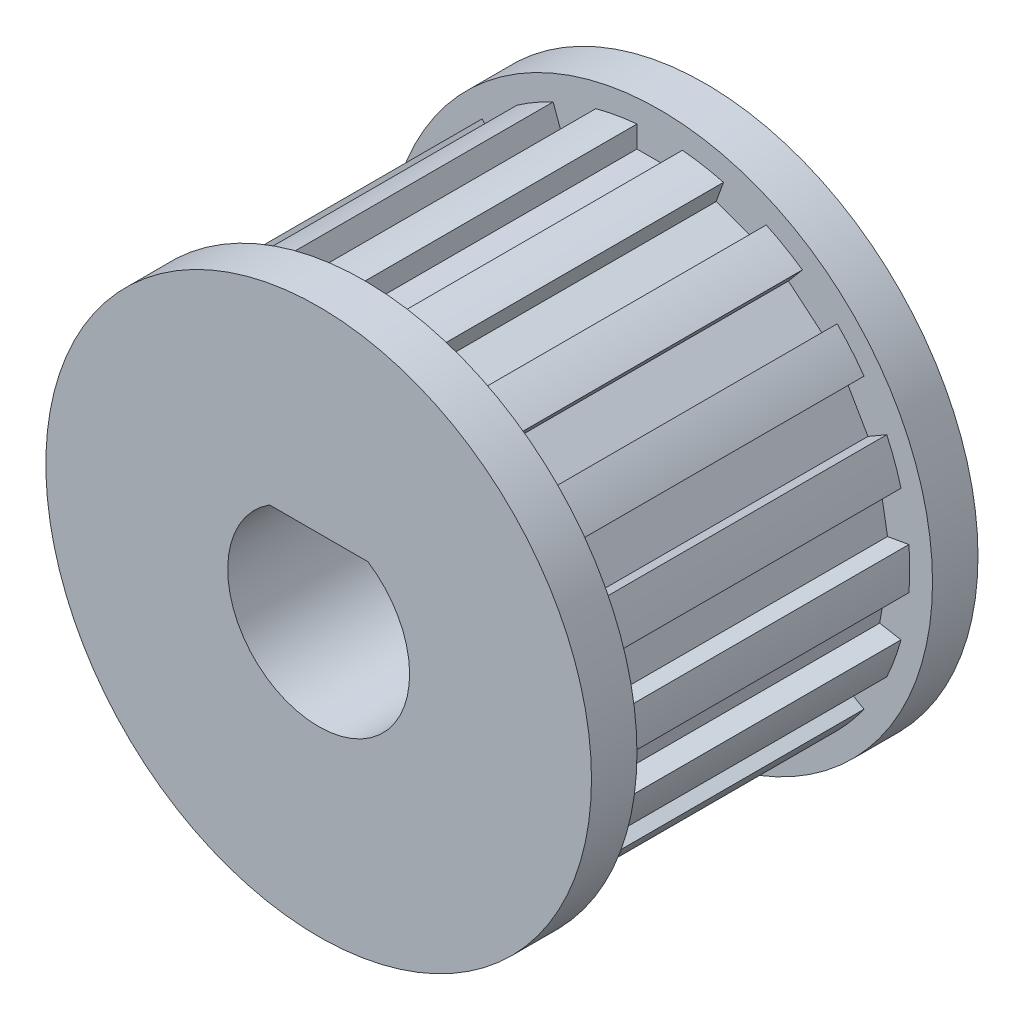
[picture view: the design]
ISO-10303-21;
HEADER;
FILE_DESCRIPTION(('STEP AP214'),'2;1');
FILE_NAME('part.step','',(''),(''),'','','');
FILE_SCHEMA(('AUTOMOTIVE_DESIGN { 1 0 10303 214 1 1 1 1 }'));
ENDSEC;
DATA;
#1=APPLICATION_CONTEXT('core data for automotive mechanical design processes');
#2=APPLICATION_PROTOCOL_DEFINITION('international standard','automotive_design',2000,#1);
#3=PRODUCT_CONTEXT('',#1,'mechanical');
#4=PRODUCT('Part','Part','',(#3));
#5=PRODUCT_RELATED_PRODUCT_CATEGORY('part','',(#4));
#6=PRODUCT_DEFINITION_FORMATION('','',#4);
#7=PRODUCT_DEFINITION_CONTEXT('part definition',#1,'design');
#8=PRODUCT_DEFINITION('design','',#6,#7);
#9=PRODUCT_DEFINITION_SHAPE('','',#8);
#10=(LENGTH_UNIT() NAMED_UNIT(*) SI_UNIT(.MILLI.,.METRE.));
#11=(NAMED_UNIT(*) PLANE_ANGLE_UNIT() SI_UNIT($,.RADIAN.));
#12=(NAMED_UNIT(*) SI_UNIT($,.STERADIAN.) SOLID_ANGLE_UNIT());
#13=UNCERTAINTY_MEASURE_WITH_UNIT(LENGTH_MEASURE(1.E-05),#10,'distance_accuracy_value','');
#14=(GEOMETRIC_REPRESENTATION_CONTEXT(3) GLOBAL_UNCERTAINTY_ASSIGNED_CONTEXT((#13)) GLOBAL_UNIT_ASSIGNED_CONTEXT((#10,
#11,#12)) REPRESENTATION_CONTEXT('',''));
#15=CARTESIAN_POINT('',(0.,0.,0.));
#16=DIRECTION('',(0.,0.,1.));
#17=DIRECTION('',(1.,0.,0.));
#18=AXIS2_PLACEMENT_3D('',#15,#16,#17);
#19=CARTESIAN_POINT('',(0.,0.,7.5));
#20=DIRECTION('',(0.,0.,-1.));
#21=DIRECTION('',(-1.,0.,0.));
#22=AXIS2_PLACEMENT_3D('',#19,#20,#21);
#23=CYLINDRICAL_SURFACE('',#22,5.5);
#24=CARTESIAN_POINT('',(0.,0.,7.5));
#25=DIRECTION('',(0.,0.,1.));
#26=DIRECTION('',(1.,0.,0.));
#27=AXIS2_PLACEMENT_3D('',#24,#25,#26);
#28=CIRCLE('',#27,5.5);
#29=CARTESIAN_POINT('',(1.40347516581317,5.31791852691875,7.5));
#30=VERTEX_POINT('',#29);
#31=CARTESIAN_POINT('',(0.500000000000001,5.47722557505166,7.5));
#32=VERTEX_POINT('',#31);
#33=EDGE_CURVE('E982',#30,#32,#28,.T.);
#34=ORIENTED_EDGE('',*,*,#33,.F.);
#35=DIRECTION('',(0.,0.,-1.));
#36=VECTOR('',#35,1.);
#37=CARTESIAN_POINT('',(1.40347516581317,5.31791852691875,7.5));
#38=LINE('',#37,#36);
#39=CARTESIAN_POINT('',(1.40347516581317,5.31791852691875,1.));
#40=VERTEX_POINT('',#39);
#41=EDGE_CURVE('E523',#30,#40,#38,.T.);
#42=ORIENTED_EDGE('',*,*,#41,.T.);
#43=CARTESIAN_POINT('',(0.,0.,1.));
#44=DIRECTION('',(0.,0.,1.));
#45=DIRECTION('',(1.,0.,0.));
#46=AXIS2_PLACEMENT_3D('',#43,#44,#45);
#47=CIRCLE('',#46,5.5);
#48=CARTESIAN_POINT('',(0.500000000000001,5.47722557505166,1.));
#49=VERTEX_POINT('',#48);
#50=EDGE_CURVE('E978',#40,#49,#47,.T.);
#51=ORIENTED_EDGE('',*,*,#50,.T.);
#52=DIRECTION('',(0.,0.,-1.));
#53=VECTOR('',#52,1.);
#54=CARTESIAN_POINT('',(0.5,5.47722557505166,7.5));
#55=LINE('',#54,#53);
#56=EDGE_CURVE('E994',#49,#32,#55,.F.);
#57=ORIENTED_EDGE('',*,*,#56,.T.);
#58=EDGE_LOOP('',(#34,#42,#51,#57));
#59=FACE_BOUND('',#58,.T.);
#60=ADVANCED_FACE('F30',(#59),#23,.T.);
#61=CARTESIAN_POINT('',(3.1376705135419,4.51719202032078,1.));
#62=VERTEX_POINT('',#61);
#63=CARTESIAN_POINT('',(2.34316778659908,4.97589838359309,1.));
#64=VERTEX_POINT('',#63);
#65=EDGE_CURVE('E1085',#62,#64,#47,.T.);
#66=ORIENTED_EDGE('',*,*,#65,.T.);
#67=DIRECTION('',(0.,0.,-1.));
#68=VECTOR('',#67,1.);
#69=CARTESIAN_POINT('',(2.34316778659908,4.97589838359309,7.5));
#70=LINE('',#69,#68);
#71=CARTESIAN_POINT('',(2.34316778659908,4.97589838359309,7.5));
#72=VERTEX_POINT('',#71);
#73=EDGE_CURVE('E496',#64,#72,#70,.F.);
#74=ORIENTED_EDGE('',*,*,#73,.T.);
#75=CARTESIAN_POINT('',(3.1376705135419,4.51719202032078,7.5));
#76=VERTEX_POINT('',#75);
#77=EDGE_CURVE('E1073',#76,#72,#28,.T.);
#78=ORIENTED_EDGE('',*,*,#77,.F.);
#79=DIRECTION('',(0.,0.,-1.));
#80=VECTOR('',#79,1.);
#81=CARTESIAN_POINT('',(3.1376705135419,4.51719202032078,7.5));
#82=LINE('',#81,#80);
#83=EDGE_CURVE('E547',#76,#62,#82,.T.);
#84=ORIENTED_EDGE('',*,*,#83,.T.);
#85=EDGE_LOOP('',(#66,#74,#78,#84));
#86=FACE_BOUND('',#85,.T.);
#87=ADVANCED_FACE('F1099',(#86),#23,.T.);
#88=CARTESIAN_POINT('',(4.49341649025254,3.1716254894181,1.));
#89=VERTEX_POINT('',#88);
#90=CARTESIAN_POINT('',(3.90371495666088,3.87440441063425,1.));
#91=VERTEX_POINT('',#90);
#92=EDGE_CURVE('E1184',#89,#91,#47,.T.);
#93=ORIENTED_EDGE('',*,*,#92,.T.);
#94=DIRECTION('',(0.,0.,-1.));
#95=VECTOR('',#94,1.);
#96=CARTESIAN_POINT('',(3.90371495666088,3.87440441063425,7.5));
#97=LINE('',#96,#95);
#98=CARTESIAN_POINT('',(3.90371495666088,3.87440441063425,7.5));
#99=VERTEX_POINT('',#98);
#100=EDGE_CURVE('E543',#91,#99,#97,.F.);
#101=ORIENTED_EDGE('',*,*,#100,.T.);
#102=CARTESIAN_POINT('',(4.49341649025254,3.1716254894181,7.5));
#103=VERTEX_POINT('',#102);
#104=EDGE_CURVE('E1070',#103,#99,#28,.T.);
#105=ORIENTED_EDGE('',*,*,#104,.F.);
#106=DIRECTION('',(0.,0.,-1.));
#107=VECTOR('',#106,1.);
#108=CARTESIAN_POINT('',(4.49341649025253,3.1716254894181,7.5));
#109=LINE('',#108,#107);
#110=EDGE_CURVE('E573',#103,#89,#109,.T.);
#111=ORIENTED_EDGE('',*,*,#110,.T.);
#112=EDGE_LOOP('',(#93,#101,#105,#111));
#113=FACE_BOUND('',#112,.T.);
#114=ADVANCED_FACE('F1104',(#113),#23,.T.);
#115=CARTESIAN_POINT('',(5.30719012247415,1.44351411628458,1.));
#116=VERTEX_POINT('',#115);
#117=CARTESIAN_POINT('',(4.99341649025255,2.30560008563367,1.));
#118=VERTEX_POINT('',#117);
#119=EDGE_CURVE('E1180',#116,#118,#47,.T.);
#120=ORIENTED_EDGE('',*,*,#119,.T.);
#121=DIRECTION('',(0.,0.,-1.));
#122=VECTOR('',#121,1.);
#123=CARTESIAN_POINT('',(4.99341649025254,2.30560008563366,7.5));
#124=LINE('',#123,#122);
#125=CARTESIAN_POINT('',(4.99341649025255,2.30560008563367,7.5));
#126=VERTEX_POINT('',#125);
#127=EDGE_CURVE('E569',#118,#126,#124,.F.);
#128=ORIENTED_EDGE('',*,*,#127,.T.);
#129=CARTESIAN_POINT('',(5.30719012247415,1.44351411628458,7.5));
#130=VERTEX_POINT('',#129);
#131=EDGE_CURVE('E1067',#130,#126,#28,.T.);
#132=ORIENTED_EDGE('',*,*,#131,.F.);
#133=DIRECTION('',(0.,0.,-1.));
#134=VECTOR('',#133,1.);
#135=CARTESIAN_POINT('',(5.30719012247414,1.44351411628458,7.5));
#136=LINE('',#135,#134);
#137=EDGE_CURVE('E599',#130,#116,#136,.T.);
#138=ORIENTED_EDGE('',*,*,#137,.T.);
#139=EDGE_LOOP('',(#120,#128,#132,#138));
#140=FACE_BOUND('',#139,.T.);
#141=ADVANCED_FACE('F1451',(#140),#23,.T.);
#142=CARTESIAN_POINT('',(5.4808383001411,-0.458706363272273,1.));
#143=VERTEX_POINT('',#142);
#144=CARTESIAN_POINT('',(5.48083830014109,0.458706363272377,1.));
#145=VERTEX_POINT('',#144);
#146=EDGE_CURVE('E1176',#143,#145,#47,.T.);
#147=ORIENTED_EDGE('',*,*,#146,.T.);
#148=DIRECTION('',(0.,0.,-1.));
#149=VECTOR('',#148,1.);
#150=CARTESIAN_POINT('',(5.48083830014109,0.458706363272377,7.5));
#151=LINE('',#150,#149);
#152=CARTESIAN_POINT('',(5.48083830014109,0.458706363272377,7.5));
#153=VERTEX_POINT('',#152);
#154=EDGE_CURVE('E596',#145,#153,#151,.F.);
#155=ORIENTED_EDGE('',*,*,#154,.T.);
#156=CARTESIAN_POINT('',(5.4808383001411,-0.458706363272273,7.5));
#157=VERTEX_POINT('',#156);
#158=EDGE_CURVE('E1064',#157,#153,#28,.T.);
#159=ORIENTED_EDGE('',*,*,#158,.F.);
#160=DIRECTION('',(0.,0.,-1.));
#161=VECTOR('',#160,1.);
#162=CARTESIAN_POINT('',(5.48083830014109,-0.458706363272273,7.5));
#163=LINE('',#162,#161);
#164=EDGE_CURVE('E625',#157,#143,#163,.T.);
#165=ORIENTED_EDGE('',*,*,#164,.T.);
#166=EDGE_LOOP('',(#147,#155,#159,#165));
#167=FACE_BOUND('',#166,.T.);
#168=ADVANCED_FACE('F1445',(#167),#23,.T.);
#169=CARTESIAN_POINT('',(4.99341649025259,-2.30560008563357,1.));
#170=VERTEX_POINT('',#169);
#171=CARTESIAN_POINT('',(5.30719012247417,-1.44351411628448,1.));
#172=VERTEX_POINT('',#171);
#173=EDGE_CURVE('E1172',#170,#172,#47,.T.);
#174=ORIENTED_EDGE('',*,*,#173,.T.);
#175=DIRECTION('',(0.,0.,-1.));
#176=VECTOR('',#175,1.);
#177=CARTESIAN_POINT('',(5.30719012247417,-1.44351411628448,7.5));
#178=LINE('',#177,#176);
#179=CARTESIAN_POINT('',(5.30719012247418,-1.44351411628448,7.5));
#180=VERTEX_POINT('',#179);
#181=EDGE_CURVE('E621',#172,#180,#178,.F.);
#182=ORIENTED_EDGE('',*,*,#181,.T.);
#183=CARTESIAN_POINT('',(4.99341649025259,-2.30560008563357,7.5));
#184=VERTEX_POINT('',#183);
#185=EDGE_CURVE('E1061',#184,#180,#28,.T.);
#186=ORIENTED_EDGE('',*,*,#185,.F.);
#187=DIRECTION('',(0.,0.,-1.));
#188=VECTOR('',#187,1.);
#189=CARTESIAN_POINT('',(4.99341649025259,-2.30560008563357,7.5));
#190=LINE('',#189,#188);
#191=EDGE_CURVE('E651',#184,#170,#190,.T.);
#192=ORIENTED_EDGE('',*,*,#191,.T.);
#193=EDGE_LOOP('',(#174,#182,#186,#192));
#194=FACE_BOUND('',#193,.T.);
#195=ADVANCED_FACE('F1439',(#194),#23,.T.);
#196=CARTESIAN_POINT('',(3.90371495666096,-3.87440441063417,1.));
#197=VERTEX_POINT('',#196);
#198=CARTESIAN_POINT('',(4.4934164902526,-3.17162548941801,1.));
#199=VERTEX_POINT('',#198);
#200=EDGE_CURVE('E1168',#197,#199,#47,.T.);
#201=ORIENTED_EDGE('',*,*,#200,.T.);
#202=DIRECTION('',(0.,0.,-1.));
#203=VECTOR('',#202,1.);
#204=CARTESIAN_POINT('',(4.4934164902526,-3.17162548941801,7.5));
#205=LINE('',#204,#203);
#206=CARTESIAN_POINT('',(4.4934164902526,-3.17162548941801,7.5));
#207=VERTEX_POINT('',#206);
#208=EDGE_CURVE('E634',#199,#207,#205,.F.);
#209=ORIENTED_EDGE('',*,*,#208,.T.);
#210=CARTESIAN_POINT('',(3.90371495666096,-3.87440441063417,7.5));
#211=VERTEX_POINT('',#210);
#212=EDGE_CURVE('E1058',#211,#207,#28,.T.);
#213=ORIENTED_EDGE('',*,*,#212,.F.);
#214=DIRECTION('',(0.,0.,-1.));
#215=VECTOR('',#214,1.);
#216=CARTESIAN_POINT('',(3.90371495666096,-3.87440441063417,7.5));
#217=LINE('',#216,#215);
#218=EDGE_CURVE('E677',#211,#197,#217,.T.);
#219=ORIENTED_EDGE('',*,*,#218,.T.);
#220=EDGE_LOOP('',(#201,#209,#213,#219));
#221=FACE_BOUND('',#220,.T.);
#222=ADVANCED_FACE('F1433',(#221),#23,.T.);
#223=CARTESIAN_POINT('',(2.34316778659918,-4.97589838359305,1.));
#224=VERTEX_POINT('',#223);
#225=CARTESIAN_POINT('',(3.13767051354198,-4.51719202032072,1.));
#226=VERTEX_POINT('',#225);
#227=EDGE_CURVE('E1164',#224,#226,#47,.T.);
#228=ORIENTED_EDGE('',*,*,#227,.T.);
#229=DIRECTION('',(0.,0.,-1.));
#230=VECTOR('',#229,1.);
#231=CARTESIAN_POINT('',(3.13767051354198,-4.51719202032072,7.5));
#232=LINE('',#231,#230);
#233=CARTESIAN_POINT('',(3.13767051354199,-4.51719202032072,7.5));
#234=VERTEX_POINT('',#233);
#235=EDGE_CURVE('E673',#226,#234,#232,.F.);
#236=ORIENTED_EDGE('',*,*,#235,.T.);
#237=CARTESIAN_POINT('',(2.34316778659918,-4.97589838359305,7.5));
#238=VERTEX_POINT('',#237);
#239=EDGE_CURVE('E1055',#238,#234,#28,.T.);
#240=ORIENTED_EDGE('',*,*,#239,.F.);
#241=DIRECTION('',(0.,0.,-1.));
#242=VECTOR('',#241,1.);
#243=CARTESIAN_POINT('',(2.34316778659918,-4.97589838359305,7.5));
#244=LINE('',#243,#242);
#245=EDGE_CURVE('E703',#238,#224,#244,.T.);
#246=ORIENTED_EDGE('',*,*,#245,.T.);
#247=EDGE_LOOP('',(#228,#236,#240,#246));
#248=FACE_BOUND('',#247,.T.);
#249=ADVANCED_FACE('F1427',(#248),#23,.T.);
#250=CARTESIAN_POINT('',(0.500000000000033,-5.47722557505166,1.));
#251=VERTEX_POINT('',#250);
#252=CARTESIAN_POINT('',(1.40347516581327,-5.31791852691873,1.));
#253=VERTEX_POINT('',#252);
#254=EDGE_CURVE('E1160',#251,#253,#47,.T.);
#255=ORIENTED_EDGE('',*,*,#254,.T.);
#256=DIRECTION('',(0.,0.,-1.));
#257=VECTOR('',#256,1.);
#258=CARTESIAN_POINT('',(1.40347516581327,-5.31791852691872,7.5));
#259=LINE('',#258,#257);
#260=CARTESIAN_POINT('',(1.40347516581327,-5.31791852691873,7.5));
#261=VERTEX_POINT('',#260);
#262=EDGE_CURVE('E700',#253,#261,#259,.F.);
#263=ORIENTED_EDGE('',*,*,#262,.T.);
#264=CARTESIAN_POINT('',(0.500000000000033,-5.47722557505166,7.5));
#265=VERTEX_POINT('',#264);
#266=EDGE_CURVE('E1052',#265,#261,#28,.T.);
#267=ORIENTED_EDGE('',*,*,#266,.F.);
#268=DIRECTION('',(0.,0.,-1.));
#269=VECTOR('',#268,1.);
#270=CARTESIAN_POINT('',(0.500000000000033,-5.47722557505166,7.5));
#271=LINE('',#270,#269);
#272=EDGE_CURVE('E729',#265,#251,#271,.T.);
#273=ORIENTED_EDGE('',*,*,#272,.T.);
#274=EDGE_LOOP('',(#255,#263,#267,#273));
#275=FACE_BOUND('',#274,.T.);
#276=ADVANCED_FACE('F1421',(#275),#23,.T.);
#277=CARTESIAN_POINT('',(-1.4034751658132,-5.31791852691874,1.));
#278=VERTEX_POINT('',#277);
#279=CARTESIAN_POINT('',(-0.499999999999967,-5.47722557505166,1.));
#280=VERTEX_POINT('',#279);
#281=EDGE_CURVE('E1156',#278,#280,#47,.T.);
#282=ORIENTED_EDGE('',*,*,#281,.T.);
#283=DIRECTION('',(0.,0.,-1.));
#284=VECTOR('',#283,1.);
#285=CARTESIAN_POINT('',(-0.499999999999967,-5.47722557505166,7.5));
#286=LINE('',#285,#284);
#287=CARTESIAN_POINT('',(-0.499999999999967,-5.47722557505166,7.5));
#288=VERTEX_POINT('',#287);
#289=EDGE_CURVE('E726',#280,#288,#286,.F.);
#290=ORIENTED_EDGE('',*,*,#289,.T.);
#291=CARTESIAN_POINT('',(-1.4034751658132,-5.31791852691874,7.5));
#292=VERTEX_POINT('',#291);
#293=EDGE_CURVE('E1049',#292,#288,#28,.T.);
#294=ORIENTED_EDGE('',*,*,#293,.F.);
#295=DIRECTION('',(0.,0.,-1.));
#296=VECTOR('',#295,1.);
#297=CARTESIAN_POINT('',(-1.4034751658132,-5.31791852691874,7.5));
#298=LINE('',#297,#296);
#299=EDGE_CURVE('E755',#292,#278,#298,.T.);
#300=ORIENTED_EDGE('',*,*,#299,.T.);
#301=EDGE_LOOP('',(#282,#290,#294,#300));
#302=FACE_BOUND('',#301,.T.);
#303=ADVANCED_FACE('F1415',(#302),#23,.T.);
#304=CARTESIAN_POINT('',(-3.13767051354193,-4.51719202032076,1.));
#305=VERTEX_POINT('',#304);
#306=CARTESIAN_POINT('',(-2.34316778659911,-4.97589838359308,1.));
#307=VERTEX_POINT('',#306);
#308=EDGE_CURVE('E1152',#305,#307,#47,.T.);
#309=ORIENTED_EDGE('',*,*,#308,.T.);
#310=DIRECTION('',(0.,0.,-1.));
#311=VECTOR('',#310,1.);
#312=CARTESIAN_POINT('',(-2.34316778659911,-4.97589838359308,7.5));
#313=LINE('',#312,#311);
#314=CARTESIAN_POINT('',(-2.34316778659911,-4.97589838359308,7.5));
#315=VERTEX_POINT('',#314);
#316=EDGE_CURVE('E738',#307,#315,#313,.F.);
#317=ORIENTED_EDGE('',*,*,#316,.T.);
#318=CARTESIAN_POINT('',(-3.13767051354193,-4.51719202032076,7.5));
#319=VERTEX_POINT('',#318);
#320=EDGE_CURVE('E1046',#319,#315,#28,.T.);
#321=ORIENTED_EDGE('',*,*,#320,.F.);
#322=DIRECTION('',(0.,0.,-1.));
#323=VECTOR('',#322,1.);
#324=CARTESIAN_POINT('',(-3.13767051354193,-4.51719202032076,7.5));
#325=LINE('',#324,#323);
#326=EDGE_CURVE('E781',#319,#305,#325,.T.);
#327=ORIENTED_EDGE('',*,*,#326,.T.);
#328=EDGE_LOOP('',(#309,#317,#321,#327));
#329=FACE_BOUND('',#328,.T.);
#330=ADVANCED_FACE('F1409',(#329),#23,.T.);
#331=CARTESIAN_POINT('',(-4.49341649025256,-3.17162548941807,1.));
#332=VERTEX_POINT('',#331);
#333=CARTESIAN_POINT('',(-3.90371495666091,-3.87440441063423,1.));
#334=VERTEX_POINT('',#333);
#335=EDGE_CURVE('E1148',#332,#334,#47,.T.);
#336=ORIENTED_EDGE('',*,*,#335,.T.);
#337=DIRECTION('',(0.,0.,-1.));
#338=VECTOR('',#337,1.);
#339=CARTESIAN_POINT('',(-3.9037149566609,-3.87440441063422,7.5));
#340=LINE('',#339,#338);
#341=CARTESIAN_POINT('',(-3.90371495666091,-3.87440441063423,7.5));
#342=VERTEX_POINT('',#341);
#343=EDGE_CURVE('E777',#334,#342,#340,.F.);
#344=ORIENTED_EDGE('',*,*,#343,.T.);
#345=CARTESIAN_POINT('',(-4.49341649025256,-3.17162548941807,7.5));
#346=VERTEX_POINT('',#345);
#347=EDGE_CURVE('E1043',#346,#342,#28,.T.);
#348=ORIENTED_EDGE('',*,*,#347,.F.);
#349=DIRECTION('',(0.,0.,-1.));
#350=VECTOR('',#349,1.);
#351=CARTESIAN_POINT('',(-4.49341649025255,-3.17162548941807,7.5));
#352=LINE('',#351,#350);
#353=EDGE_CURVE('E807',#346,#332,#352,.T.);
#354=ORIENTED_EDGE('',*,*,#353,.T.);
#355=EDGE_LOOP('',(#336,#344,#348,#354));
#356=FACE_BOUND('',#355,.T.);
#357=ADVANCED_FACE('F1403',(#356),#23,.T.);
#358=CARTESIAN_POINT('',(-5.30719012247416,-1.44351411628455,1.));
#359=VERTEX_POINT('',#358);
#360=CARTESIAN_POINT('',(-4.99341649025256,-2.30560008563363,1.));
#361=VERTEX_POINT('',#360);
#362=EDGE_CURVE('E1144',#359,#361,#47,.T.);
#363=ORIENTED_EDGE('',*,*,#362,.T.);
#364=DIRECTION('',(0.,0.,-1.));
#365=VECTOR('',#364,1.);
#366=CARTESIAN_POINT('',(-4.99341649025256,-2.30560008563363,7.5));
#367=LINE('',#366,#365);
#368=CARTESIAN_POINT('',(-4.99341649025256,-2.30560008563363,7.5));
#369=VERTEX_POINT('',#368);
#370=EDGE_CURVE('E803',#361,#369,#367,.F.);
#371=ORIENTED_EDGE('',*,*,#370,.T.);
#372=CARTESIAN_POINT('',(-5.30719012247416,-1.44351411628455,7.5));
#373=VERTEX_POINT('',#372);
#374=EDGE_CURVE('E1040',#373,#369,#28,.T.);
#375=ORIENTED_EDGE('',*,*,#374,.F.);
#376=DIRECTION('',(0.,0.,-1.));
#377=VECTOR('',#376,1.);
#378=CARTESIAN_POINT('',(-5.30719012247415,-1.44351411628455,7.5));
#379=LINE('',#378,#377);
#380=EDGE_CURVE('E833',#373,#359,#379,.T.);
#381=ORIENTED_EDGE('',*,*,#380,.T.);
#382=EDGE_LOOP('',(#363,#371,#375,#381));
#383=FACE_BOUND('',#382,.T.);
#384=ADVANCED_FACE('F1397',(#383),#23,.T.);
#385=CARTESIAN_POINT('',(-5.48083830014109,0.458706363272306,1.));
#386=VERTEX_POINT('',#385);
#387=CARTESIAN_POINT('',(-5.48083830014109,-0.45870636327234,1.));
#388=VERTEX_POINT('',#387);
#389=EDGE_CURVE('E1141',#386,#388,#47,.T.);
#390=ORIENTED_EDGE('',*,*,#389,.T.);
#391=DIRECTION('',(0.,0.,-1.));
#392=VECTOR('',#391,1.);
#393=CARTESIAN_POINT('',(-5.48083830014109,-0.45870636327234,7.5));
#394=LINE('',#393,#392);
#395=CARTESIAN_POINT('',(-5.48083830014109,-0.45870636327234,7.5));
#396=VERTEX_POINT('',#395);
#397=EDGE_CURVE('E830',#388,#396,#394,.F.);
#398=ORIENTED_EDGE('',*,*,#397,.T.);
#399=CARTESIAN_POINT('',(-5.48083830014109,0.458706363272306,7.5));
#400=VERTEX_POINT('',#399);
#401=EDGE_CURVE('E1037',#400,#396,#28,.T.);
#402=ORIENTED_EDGE('',*,*,#401,.F.);
#403=DIRECTION('',(0.,0.,-1.));
#404=VECTOR('',#403,1.);
#405=CARTESIAN_POINT('',(-5.48083830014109,0.458706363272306,7.5));
#406=LINE('',#405,#404);
#407=EDGE_CURVE('E859',#400,#386,#406,.T.);
#408=ORIENTED_EDGE('',*,*,#407,.T.);
#409=EDGE_LOOP('',(#390,#398,#402,#408));
#410=FACE_BOUND('',#409,.T.);
#411=ADVANCED_FACE('F1132',(#410),#23,.T.);
#412=CARTESIAN_POINT('',(-4.99341649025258,2.3056000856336,1.));
#413=VERTEX_POINT('',#412);
#414=CARTESIAN_POINT('',(-5.30719012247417,1.44351411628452,1.));
#415=VERTEX_POINT('',#414);
#416=EDGE_CURVE('E1139',#413,#415,#47,.T.);
#417=ORIENTED_EDGE('',*,*,#416,.T.);
#418=DIRECTION('',(0.,0.,-1.));
#419=VECTOR('',#418,1.);
#420=CARTESIAN_POINT('',(-5.30719012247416,1.44351411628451,7.5));
#421=LINE('',#420,#419);
#422=CARTESIAN_POINT('',(-5.30719012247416,1.44351411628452,7.5));
#423=VERTEX_POINT('',#422);
#424=EDGE_CURVE('E855',#415,#423,#421,.F.);
#425=ORIENTED_EDGE('',*,*,#424,.T.);
#426=CARTESIAN_POINT('',(-4.99341649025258,2.3056000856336,7.5));
#427=VERTEX_POINT('',#426);
#428=EDGE_CURVE('E1034',#427,#423,#28,.T.);
#429=ORIENTED_EDGE('',*,*,#428,.F.);
#430=DIRECTION('',(0.,0.,-1.));
#431=VECTOR('',#430,1.);
#432=CARTESIAN_POINT('',(-4.99341649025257,2.3056000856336,7.5));
#433=LINE('',#432,#431);
#434=EDGE_CURVE('E885',#427,#413,#433,.T.);
#435=ORIENTED_EDGE('',*,*,#434,.T.);
#436=EDGE_LOOP('',(#417,#425,#429,#435));
#437=FACE_BOUND('',#436,.T.);
#438=ADVANCED_FACE('F1127',(#437),#23,.T.);
#439=CARTESIAN_POINT('',(-3.90371495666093,3.8744044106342,1.));
#440=VERTEX_POINT('',#439);
#441=CARTESIAN_POINT('',(-4.49341649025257,3.17162548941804,1.));
#442=VERTEX_POINT('',#441);
#443=EDGE_CURVE('E1136',#440,#442,#47,.T.);
#444=ORIENTED_EDGE('',*,*,#443,.T.);
#445=DIRECTION('',(0.,0.,-1.));
#446=VECTOR('',#445,1.);
#447=CARTESIAN_POINT('',(-4.49341649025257,3.17162548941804,7.5));
#448=LINE('',#447,#446);
#449=CARTESIAN_POINT('',(-4.49341649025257,3.17162548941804,7.5));
#450=VERTEX_POINT('',#449);
#451=EDGE_CURVE('E868',#442,#450,#448,.F.);
#452=ORIENTED_EDGE('',*,*,#451,.T.);
#453=CARTESIAN_POINT('',(-3.90371495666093,3.8744044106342,7.5));
#454=VERTEX_POINT('',#453);
#455=EDGE_CURVE('E1032',#454,#450,#28,.T.);
#456=ORIENTED_EDGE('',*,*,#455,.F.);
#457=DIRECTION('',(0.,0.,-1.));
#458=VECTOR('',#457,1.);
#459=CARTESIAN_POINT('',(-3.90371495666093,3.8744044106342,7.5));
#460=LINE('',#459,#458);
#461=EDGE_CURVE('E911',#454,#440,#460,.T.);
#462=ORIENTED_EDGE('',*,*,#461,.T.);
#463=EDGE_LOOP('',(#444,#452,#456,#462));
#464=FACE_BOUND('',#463,.T.);
#465=ADVANCED_FACE('F1119',(#464),#23,.T.);
#466=CARTESIAN_POINT('',(-2.34316778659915,4.97589838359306,1.));
#467=VERTEX_POINT('',#466);
#468=CARTESIAN_POINT('',(-3.13767051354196,4.51719202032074,1.));
#469=VERTEX_POINT('',#468);
#470=EDGE_CURVE('E983',#467,#469,#47,.T.);
#471=ORIENTED_EDGE('',*,*,#470,.T.);
#472=DIRECTION('',(0.,0.,-1.));
#473=VECTOR('',#472,1.);
#474=CARTESIAN_POINT('',(-3.13767051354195,4.51719202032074,7.5));
#475=LINE('',#474,#473);
#476=CARTESIAN_POINT('',(-3.13767051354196,4.51719202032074,7.5));
#477=VERTEX_POINT('',#476);
#478=EDGE_CURVE('E907',#469,#477,#475,.F.);
#479=ORIENTED_EDGE('',*,*,#478,.T.);
#480=CARTESIAN_POINT('',(-2.34316778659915,4.97589838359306,7.5));
#481=VERTEX_POINT('',#480);
#482=EDGE_CURVE('E988',#481,#477,#28,.T.);
#483=ORIENTED_EDGE('',*,*,#482,.F.);
#484=DIRECTION('',(0.,0.,-1.));
#485=VECTOR('',#484,1.);
#486=CARTESIAN_POINT('',(-2.34316778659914,4.97589838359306,7.5));
#487=LINE('',#486,#485);
#488=EDGE_CURVE('E11',#481,#467,#487,.T.);
#489=ORIENTED_EDGE('',*,*,#488,.T.);
#490=EDGE_LOOP('',(#471,#479,#483,#489));
#491=FACE_BOUND('',#490,.T.);
#492=ADVANCED_FACE('F1029',(#491),#23,.T.);
#493=CARTESIAN_POINT('',(0.,0.,3.5));
#494=DIRECTION('',(0.,0.,1.));
#495=DIRECTION('',(1.,0.,0.));
#496=AXIS2_PLACEMENT_3D('',#493,#494,#495);
#497=CYLINDRICAL_SURFACE('',#496,2.);
#498=DIRECTION('',(0.,0.,1.));
#499=VECTOR('',#498,1.);
#500=CARTESIAN_POINT('',(-1.08151518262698,1.68235695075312,3.5));
#501=LINE('',#500,#499);
#502=CARTESIAN_POINT('',(-1.08151518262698,1.68235695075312,3.5));
#503=VERTEX_POINT('',#502);
#504=CARTESIAN_POINT('',(-1.08151518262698,1.68235695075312,8.5));
#505=VERTEX_POINT('',#504);
#506=EDGE_CURVE('E970',#503,#505,#501,.T.);
#507=ORIENTED_EDGE('',*,*,#506,.T.);
#508=CARTESIAN_POINT('',(0.,0.,8.5));
#509=DIRECTION('',(0.,0.,1.));
#510=DIRECTION('',(1.,0.,0.));
#511=AXIS2_PLACEMENT_3D('',#508,#509,#510);
#512=CIRCLE('',#511,2.);
#513=CARTESIAN_POINT('',(1.08151518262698,1.68235695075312,8.5));
#514=VERTEX_POINT('',#513);
#515=EDGE_CURVE('E959',#505,#514,#512,.T.);
#516=ORIENTED_EDGE('',*,*,#515,.T.);
#517=DIRECTION('',(0.,0.,1.));
#518=VECTOR('',#517,1.);
#519=CARTESIAN_POINT('',(1.08151518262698,1.68235695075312,3.5));
#520=LINE('',#519,#518);
#521=CARTESIAN_POINT('',(1.08151518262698,1.68235695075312,3.5));
#522=VERTEX_POINT('',#521);
#523=EDGE_CURVE('E967',#522,#514,#520,.T.);
#524=ORIENTED_EDGE('',*,*,#523,.F.);
#525=CARTESIAN_POINT('',(0.,0.,3.5));
#526=DIRECTION('',(0.,0.,-1.));
#527=DIRECTION('',(-1.,0.,0.));
#528=AXIS2_PLACEMENT_3D('',#525,#526,#527);
#529=CIRCLE('',#528,2.);
#530=EDGE_CURVE('E957',#503,#522,#529,.T.);
#531=ORIENTED_EDGE('',*,*,#530,.F.);
#532=EDGE_LOOP('',(#507,#516,#524,#531));
#533=FACE_BOUND('',#532,.T.);
#534=CARTESIAN_POINT('',(0.,0.,0.));
#535=DIRECTION('',(0.,0.,-1.));
#536=DIRECTION('',(-1.,0.,0.));
#537=AXIS2_PLACEMENT_3D('',#534,#535,#536);
#538=CIRCLE('',#537,2.);
#539=CARTESIAN_POINT('',(-2.,0.,0.));
#540=VERTEX_POINT('',#539);
#541=EDGE_CURVE('E954',#540,#540,#538,.T.);
#542=ORIENTED_EDGE('',*,*,#541,.T.);
#543=EDGE_LOOP('',(#542));
#544=FACE_BOUND('',#543,.T.);
#545=ADVANCED_FACE('F1118',(#533,#544),#497,.F.);
#546=CARTESIAN_POINT('',(-1.08151518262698,1.68235695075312,3.5));
#547=DIRECTION('',(0.,-1.,0.));
#548=DIRECTION('',(0.,0.,-1.));
#549=AXIS2_PLACEMENT_3D('',#546,#547,#548);
#550=PLANE('',#549);
#551=DIRECTION('',(1.,0.,0.));
#552=VECTOR('',#551,1.);
#553=CARTESIAN_POINT('',(-1.08151518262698,1.68235695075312,3.5));
#554=LINE('',#553,#552);
#555=EDGE_CURVE('E964',#503,#522,#554,.T.);
#556=ORIENTED_EDGE('',*,*,#555,.T.);
#557=ORIENTED_EDGE('',*,*,#523,.T.);
#558=DIRECTION('',(1.,0.,0.));
#559=VECTOR('',#558,1.);
#560=CARTESIAN_POINT('',(-1.08151518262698,1.68235695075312,8.5));
#561=LINE('',#560,#559);
#562=EDGE_CURVE('E961',#505,#514,#561,.T.);
#563=ORIENTED_EDGE('',*,*,#562,.F.);
#564=ORIENTED_EDGE('',*,*,#506,.F.);
#565=EDGE_LOOP('',(#556,#557,#563,#564));
#566=FACE_BOUND('',#565,.T.);
#567=ADVANCED_FACE('F1124',(#566),#550,.T.);
#568=CARTESIAN_POINT('',(0.,0.,7.5));
#569=DIRECTION('',(0.,0.,1.));
#570=DIRECTION('',(1.,0.,0.));
#571=AXIS2_PLACEMENT_3D('',#568,#569,#570);
#572=PLANE('',#571);
#573=ORIENTED_EDGE('',*,*,#77,.T.);
#574=DIRECTION('',(-0.342020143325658,-0.939692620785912,0.));
#575=VECTOR('',#574,1.);
#576=CARTESIAN_POINT('',(4.91610817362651,12.044993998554,7.5));
#577=LINE('',#576,#575);
#578=CARTESIAN_POINT('',(2.17994702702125,4.52745303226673,7.5));
#579=VERTEX_POINT('',#578);
#580=EDGE_CURVE('E506',#72,#579,#577,.T.);
#581=ORIENTED_EDGE('',*,*,#580,.T.);
#582=DIRECTION('',(0.939692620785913,-0.342020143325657,0.));
#583=VECTOR('',#582,1.);
#584=CARTESIAN_POINT('',(1.24025440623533,4.86947317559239,7.5));
#585=LINE('',#584,#583);
#586=CARTESIAN_POINT('',(1.24025440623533,4.86947317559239,7.5));
#587=VERTEX_POINT('',#586);
#588=EDGE_CURVE('E505',#587,#579,#585,.T.);
#589=ORIENTED_EDGE('',*,*,#588,.F.);
#590=DIRECTION('',(0.342020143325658,0.939692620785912,0.));
#591=VECTOR('',#590,1.);
#592=CARTESIAN_POINT('',(1.24025440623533,4.86947317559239,7.5));
#593=LINE('',#592,#591);
#594=EDGE_CURVE('E515',#587,#30,#593,.T.);
#595=ORIENTED_EDGE('',*,*,#594,.T.);
#596=ORIENTED_EDGE('',*,*,#33,.T.);
#597=DIRECTION('',(0.,-1.,0.));
#598=VECTOR('',#597,1.);
#599=CARTESIAN_POINT('',(0.500000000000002,13.,7.5));
#600=LINE('',#599,#598);
#601=CARTESIAN_POINT('',(0.500000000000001,5.,7.5));
#602=VERTEX_POINT('',#601);
#603=EDGE_CURVE('E944',#32,#602,#600,.T.);
#604=ORIENTED_EDGE('',*,*,#603,.T.);
#605=DIRECTION('',(1.,0.,0.));
#606=VECTOR('',#605,1.);
#607=CARTESIAN_POINT('',(-0.5,5.,7.5));
#608=LINE('',#607,#606);
#609=CARTESIAN_POINT('',(-0.5,5.,7.5));
#610=VERTEX_POINT('',#609);
#611=EDGE_CURVE('E946',#610,#602,#608,.T.);
#612=ORIENTED_EDGE('',*,*,#611,.F.);
#613=DIRECTION('',(0.,1.,0.));
#614=VECTOR('',#613,1.);
#615=CARTESIAN_POINT('',(-0.5,5.,7.5));
#616=LINE('',#615,#614);
#617=CARTESIAN_POINT('',(-0.5,5.47722557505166,7.5));
#618=VERTEX_POINT('',#617);
#619=EDGE_CURVE('E941',#610,#618,#616,.T.);
#620=ORIENTED_EDGE('',*,*,#619,.T.);
#621=CARTESIAN_POINT('',(-1.40347516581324,5.31791852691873,7.5));
#622=VERTEX_POINT('',#621);
#623=EDGE_CURVE('E984',#618,#622,#28,.T.);
#624=ORIENTED_EDGE('',*,*,#623,.T.);
#625=DIRECTION('',(0.342020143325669,-0.939692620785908,0.));
#626=VECTOR('',#625,1.);
#627=CARTESIAN_POINT('',(-3.97641555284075,12.3870141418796,7.5));
#628=LINE('',#627,#626);
#629=CARTESIAN_POINT('',(-1.24025440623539,4.86947317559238,7.5));
#630=VERTEX_POINT('',#629);
#631=EDGE_CURVE('E924',#622,#630,#628,.T.);
#632=ORIENTED_EDGE('',*,*,#631,.T.);
#633=DIRECTION('',(0.939692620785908,0.34202014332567,0.));
#634=VECTOR('',#633,1.);
#635=CARTESIAN_POINT('',(-2.1799470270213,4.52745303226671,7.5));
#636=LINE('',#635,#634);
#637=CARTESIAN_POINT('',(-2.1799470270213,4.52745303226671,7.5));
#638=VERTEX_POINT('',#637);
#639=EDGE_CURVE('E926',#638,#630,#636,.T.);
#640=ORIENTED_EDGE('',*,*,#639,.F.);
#641=DIRECTION('',(-0.342020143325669,0.939692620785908,0.));
#642=VECTOR('',#641,1.);
#643=CARTESIAN_POINT('',(-2.1799470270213,4.52745303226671,7.5));
#644=LINE('',#643,#642);
#645=EDGE_CURVE('E921',#638,#481,#644,.T.);
#646=ORIENTED_EDGE('',*,*,#645,.T.);
#647=ORIENTED_EDGE('',*,*,#482,.T.);
#648=DIRECTION('',(0.64278760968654,-0.766044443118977,0.));
#649=VECTOR('',#648,1.);
#650=CARTESIAN_POINT('',(-7.97321670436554,10.27997156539,7.5));
#651=LINE('',#650,#649);
#652=CARTESIAN_POINT('',(-2.83091582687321,4.15161602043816,7.5));
#653=VERTEX_POINT('',#652);
#654=EDGE_CURVE('E896',#477,#653,#651,.T.);
#655=ORIENTED_EDGE('',*,*,#654,.T.);
#656=DIRECTION('',(0.766044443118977,0.642787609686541,0.));
#657=VECTOR('',#656,1.);
#658=CARTESIAN_POINT('',(-3.59696026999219,3.50882841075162,7.5));
#659=LINE('',#658,#657);
#660=CARTESIAN_POINT('',(-3.59696026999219,3.50882841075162,7.5));
#661=VERTEX_POINT('',#660);
#662=EDGE_CURVE('E895',#661,#653,#659,.T.);
#663=ORIENTED_EDGE('',*,*,#662,.F.);
#664=DIRECTION('',(-0.64278760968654,0.766044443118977,0.));
#665=VECTOR('',#664,1.);
#666=CARTESIAN_POINT('',(-3.59696026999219,3.50882841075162,7.5));
#667=LINE('',#666,#665);
#668=EDGE_CURVE('E888',#661,#454,#667,.T.);
#669=ORIENTED_EDGE('',*,*,#668,.T.);
#670=ORIENTED_EDGE('',*,*,#455,.T.);
#671=DIRECTION('',(0.86602540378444,-0.499999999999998,0.));
#672=VECTOR('',#671,1.);
#673=CARTESIAN_POINT('',(-11.0083302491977,6.9330127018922,7.5));
#674=LINE('',#673,#672);
#675=CARTESIAN_POINT('',(-4.0801270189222,2.93301270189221,7.5));
#676=VERTEX_POINT('',#675);
#677=EDGE_CURVE('E872',#450,#676,#674,.T.);
#678=ORIENTED_EDGE('',*,*,#677,.T.);
#679=DIRECTION('',(0.499999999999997,0.86602540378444,0.));
#680=VECTOR('',#679,1.);
#681=CARTESIAN_POINT('',(-4.5801270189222,2.06698729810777,7.5));
#682=LINE('',#681,#680);
#683=CARTESIAN_POINT('',(-4.5801270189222,2.06698729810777,7.5));
#684=VERTEX_POINT('',#683);
#685=EDGE_CURVE('E866',#684,#676,#682,.T.);
#686=ORIENTED_EDGE('',*,*,#685,.F.);
#687=DIRECTION('',(-0.86602540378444,0.499999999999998,0.));
#688=VECTOR('',#687,1.);
#689=CARTESIAN_POINT('',(-4.5801270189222,2.06698729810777,7.5));
#690=LINE('',#689,#688);
#691=EDGE_CURVE('E862',#684,#427,#690,.T.);
#692=ORIENTED_EDGE('',*,*,#691,.T.);
#693=ORIENTED_EDGE('',*,*,#428,.T.);
#694=DIRECTION('',(0.984807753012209,-0.173648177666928,0.));
#695=VECTOR('',#694,1.);
#696=CARTESIAN_POINT('',(-12.7156767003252,2.74983018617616,7.5));
#697=LINE('',#696,#695);
#698=CARTESIAN_POINT('',(-4.83721467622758,1.36064476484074,7.5));
#699=VERTEX_POINT('',#698);
#700=EDGE_CURVE('E844',#423,#699,#697,.T.);
#701=ORIENTED_EDGE('',*,*,#700,.T.);
#702=DIRECTION('',(0.173648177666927,0.984807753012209,0.));
#703=VECTOR('',#702,1.);
#704=CARTESIAN_POINT('',(-5.01086285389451,0.375837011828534,7.5));
#705=LINE('',#704,#703);
#706=CARTESIAN_POINT('',(-5.01086285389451,0.375837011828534,7.5));
#707=VERTEX_POINT('',#706);
#708=EDGE_CURVE('E843',#707,#699,#705,.T.);
#709=ORIENTED_EDGE('',*,*,#708,.F.);
#710=DIRECTION('',(-0.984807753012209,0.173648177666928,0.));
#711=VECTOR('',#710,1.);
#712=CARTESIAN_POINT('',(-5.01086285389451,0.375837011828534,7.5));
#713=LINE('',#712,#711);
#714=EDGE_CURVE('E836',#707,#400,#713,.T.);
#715=ORIENTED_EDGE('',*,*,#714,.T.);
#716=ORIENTED_EDGE('',*,*,#401,.T.);
#717=DIRECTION('',(0.984807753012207,0.173648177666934,0.));
#718=VECTOR('',#717,1.);
#719=CARTESIAN_POINT('',(-12.8893248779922,-1.76502243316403,7.5));
#720=LINE('',#719,#718);
#721=CARTESIAN_POINT('',(-5.0108628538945,-0.375837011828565,7.5));
#722=VERTEX_POINT('',#721);
#723=EDGE_CURVE('E820',#396,#722,#720,.T.);
#724=ORIENTED_EDGE('',*,*,#723,.T.);
#725=DIRECTION('',(-0.173648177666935,0.984807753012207,0.));
#726=VECTOR('',#725,1.);
#727=CARTESIAN_POINT('',(-4.83721467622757,-1.36064476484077,7.5));
#728=LINE('',#727,#726);
#729=CARTESIAN_POINT('',(-4.83721467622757,-1.36064476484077,7.5));
#730=VERTEX_POINT('',#729);
#731=EDGE_CURVE('E822',#730,#722,#728,.T.);
#732=ORIENTED_EDGE('',*,*,#731,.F.);
#733=DIRECTION('',(-0.984807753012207,-0.173648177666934,0.));
#734=VECTOR('',#733,1.);
#735=CARTESIAN_POINT('',(-4.83721467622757,-1.36064476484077,7.5));
#736=LINE('',#735,#734);
#737=EDGE_CURVE('E817',#730,#373,#736,.T.);
#738=ORIENTED_EDGE('',*,*,#737,.T.);
#739=ORIENTED_EDGE('',*,*,#374,.T.);
#740=DIRECTION('',(0.866025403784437,0.500000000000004,0.));
#741=VECTOR('',#740,1.);
#742=CARTESIAN_POINT('',(-11.5083302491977,-6.06698729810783,7.5));
#743=LINE('',#742,#741);
#744=CARTESIAN_POINT('',(-4.58012701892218,-2.0669872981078,7.5));
#745=VERTEX_POINT('',#744);
#746=EDGE_CURVE('E792',#369,#745,#743,.T.);
#747=ORIENTED_EDGE('',*,*,#746,.T.);
#748=DIRECTION('',(-0.500000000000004,0.866025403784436,0.));
#749=VECTOR('',#748,1.);
#750=CARTESIAN_POINT('',(-4.08012701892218,-2.93301270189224,7.5));
#751=LINE('',#750,#749);
#752=CARTESIAN_POINT('',(-4.08012701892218,-2.93301270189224,7.5));
#753=VERTEX_POINT('',#752);
#754=EDGE_CURVE('E791',#753,#745,#751,.T.);
#755=ORIENTED_EDGE('',*,*,#754,.F.);
#756=DIRECTION('',(-0.866025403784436,-0.500000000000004,0.));
#757=VECTOR('',#756,1.);
#758=CARTESIAN_POINT('',(-4.08012701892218,-2.93301270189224,7.5));
#759=LINE('',#758,#757);
#760=EDGE_CURVE('E784',#753,#346,#759,.T.);
#761=ORIENTED_EDGE('',*,*,#760,.T.);
#762=ORIENTED_EDGE('',*,*,#347,.T.);
#763=DIRECTION('',(0.642787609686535,0.766044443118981,0.));
#764=VECTOR('',#763,1.);
#765=CARTESIAN_POINT('',(-8.73926114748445,-9.63718395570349,7.5));
#766=LINE('',#765,#764);
#767=CARTESIAN_POINT('',(-3.59696026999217,-3.50882841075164,7.5));
#768=VERTEX_POINT('',#767);
#769=EDGE_CURVE('E766',#342,#768,#766,.T.);
#770=ORIENTED_EDGE('',*,*,#769,.T.);
#771=DIRECTION('',(-0.766044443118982,0.642787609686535,0.));
#772=VECTOR('',#771,1.);
#773=CARTESIAN_POINT('',(-2.83091582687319,-4.15161602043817,7.5));
#774=LINE('',#773,#772);
#775=CARTESIAN_POINT('',(-2.83091582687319,-4.15161602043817,7.5));
#776=VERTEX_POINT('',#775);
#777=EDGE_CURVE('E765',#776,#768,#774,.T.);
#778=ORIENTED_EDGE('',*,*,#777,.F.);
#779=DIRECTION('',(-0.642787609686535,-0.766044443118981,0.));
#780=VECTOR('',#779,1.);
#781=CARTESIAN_POINT('',(-2.83091582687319,-4.15161602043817,7.5));
#782=LINE('',#781,#780);
#783=EDGE_CURVE('E758',#776,#319,#782,.T.);
#784=ORIENTED_EDGE('',*,*,#783,.T.);
#785=ORIENTED_EDGE('',*,*,#320,.T.);
#786=DIRECTION('',(0.342020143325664,0.93969262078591,0.));
#787=VECTOR('',#786,1.);
#788=CARTESIAN_POINT('',(-4.91610817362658,-12.044993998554,7.5));
#789=LINE('',#788,#787);
#790=CARTESIAN_POINT('',(-2.17994702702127,-4.52745303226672,7.5));
#791=VERTEX_POINT('',#790);
#792=EDGE_CURVE('E742',#315,#791,#789,.T.);
#793=ORIENTED_EDGE('',*,*,#792,.T.);
#794=DIRECTION('',(-0.939692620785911,0.342020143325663,0.));
#795=VECTOR('',#794,1.);
#796=CARTESIAN_POINT('',(-1.24025440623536,-4.86947317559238,7.5));
#797=LINE('',#796,#795);
#798=CARTESIAN_POINT('',(-1.24025440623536,-4.86947317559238,7.5));
#799=VERTEX_POINT('',#798);
#800=EDGE_CURVE('E736',#799,#791,#797,.T.);
#801=ORIENTED_EDGE('',*,*,#800,.F.);
#802=DIRECTION('',(-0.342020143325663,-0.93969262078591,0.));
#803=VECTOR('',#802,1.);
#804=CARTESIAN_POINT('',(-1.24025440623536,-4.86947317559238,7.5));
#805=LINE('',#804,#803);
#806=EDGE_CURVE('E732',#799,#292,#805,.T.);
#807=ORIENTED_EDGE('',*,*,#806,.T.);
#808=ORIENTED_EDGE('',*,*,#293,.T.);
#809=DIRECTION('',(0.,1.,0.));
#810=VECTOR('',#809,1.);
#811=CARTESIAN_POINT('',(-0.499999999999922,-13.,7.5));
#812=LINE('',#811,#810);
#813=CARTESIAN_POINT('',(-0.49999999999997,-5.,7.5));
#814=VERTEX_POINT('',#813);
#815=EDGE_CURVE('E716',#288,#814,#812,.T.);
#816=ORIENTED_EDGE('',*,*,#815,.T.);
#817=DIRECTION('',(-1.,0.,0.));
#818=VECTOR('',#817,1.);
#819=CARTESIAN_POINT('',(0.500000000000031,-5.,7.5));
#820=LINE('',#819,#818);
#821=CARTESIAN_POINT('',(0.500000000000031,-5.,7.5));
#822=VERTEX_POINT('',#821);
#823=EDGE_CURVE('E718',#822,#814,#820,.T.);
#824=ORIENTED_EDGE('',*,*,#823,.F.);
#825=DIRECTION('',(0.,-1.,0.));
#826=VECTOR('',#825,1.);
#827=CARTESIAN_POINT('',(0.500000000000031,-5.,7.5));
#828=LINE('',#827,#826);
#829=EDGE_CURVE('E713',#822,#265,#828,.T.);
#830=ORIENTED_EDGE('',*,*,#829,.T.);
#831=ORIENTED_EDGE('',*,*,#266,.T.);
#832=DIRECTION('',(-0.342020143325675,0.939692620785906,0.));
#833=VECTOR('',#832,1.);
#834=CARTESIAN_POINT('',(3.97641555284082,-12.3870141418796,7.5));
#835=LINE('',#834,#833);
#836=CARTESIAN_POINT('',(1.24025440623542,-4.86947317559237,7.5));
#837=VERTEX_POINT('',#836);
#838=EDGE_CURVE('E690',#261,#837,#835,.T.);
#839=ORIENTED_EDGE('',*,*,#838,.T.);
#840=DIRECTION('',(-0.939692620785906,-0.342020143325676,0.));
#841=VECTOR('',#840,1.);
#842=CARTESIAN_POINT('',(2.17994702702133,-4.52745303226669,7.5));
#843=LINE('',#842,#841);
#844=CARTESIAN_POINT('',(2.17994702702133,-4.52745303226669,7.5));
#845=VERTEX_POINT('',#844);
#846=EDGE_CURVE('E692',#845,#837,#843,.T.);
#847=ORIENTED_EDGE('',*,*,#846,.F.);
#848=DIRECTION('',(0.342020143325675,-0.939692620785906,0.));
#849=VECTOR('',#848,1.);
#850=CARTESIAN_POINT('',(2.17994702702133,-4.52745303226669,7.5));
#851=LINE('',#850,#849);
#852=EDGE_CURVE('E687',#845,#238,#851,.T.);
#853=ORIENTED_EDGE('',*,*,#852,.T.);
#854=ORIENTED_EDGE('',*,*,#239,.T.);
#855=DIRECTION('',(-0.642787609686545,0.766044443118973,0.));
#856=VECTOR('',#855,1.);
#857=CARTESIAN_POINT('',(7.9732167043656,-10.2799715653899,7.5));
#858=LINE('',#857,#856);
#859=CARTESIAN_POINT('',(2.83091582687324,-4.15161602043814,7.5));
#860=VERTEX_POINT('',#859);
#861=EDGE_CURVE('E662',#234,#860,#858,.T.);
#862=ORIENTED_EDGE('',*,*,#861,.T.);
#863=DIRECTION('',(-0.766044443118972,-0.642787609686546,0.));
#864=VECTOR('',#863,1.);
#865=CARTESIAN_POINT('',(3.59696026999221,-3.50882841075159,7.5));
#866=LINE('',#865,#864);
#867=CARTESIAN_POINT('',(3.59696026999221,-3.50882841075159,7.5));
#868=VERTEX_POINT('',#867);
#869=EDGE_CURVE('E661',#868,#860,#866,.T.);
#870=ORIENTED_EDGE('',*,*,#869,.F.);
#871=DIRECTION('',(0.642787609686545,-0.766044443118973,0.));
#872=VECTOR('',#871,1.);
#873=CARTESIAN_POINT('',(3.59696026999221,-3.50882841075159,7.5));
#874=LINE('',#873,#872);
#875=EDGE_CURVE('E654',#868,#211,#874,.T.);
#876=ORIENTED_EDGE('',*,*,#875,.T.);
#877=ORIENTED_EDGE('',*,*,#212,.T.);
#878=DIRECTION('',(-0.866025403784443,0.499999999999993,0.));
#879=VECTOR('',#878,1.);
#880=CARTESIAN_POINT('',(11.0083302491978,-6.93301270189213,7.5));
#881=LINE('',#880,#879);
#882=CARTESIAN_POINT('',(4.08012701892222,-2.93301270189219,7.5));
#883=VERTEX_POINT('',#882);
#884=EDGE_CURVE('E638',#207,#883,#881,.T.);
#885=ORIENTED_EDGE('',*,*,#884,.T.);
#886=DIRECTION('',(-0.499999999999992,-0.866025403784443,0.));
#887=VECTOR('',#886,1.);
#888=CARTESIAN_POINT('',(4.58012701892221,-2.06698729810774,7.5));
#889=LINE('',#888,#887);
#890=CARTESIAN_POINT('',(4.58012701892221,-2.06698729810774,7.5));
#891=VERTEX_POINT('',#890);
#892=EDGE_CURVE('E632',#891,#883,#889,.T.);
#893=ORIENTED_EDGE('',*,*,#892,.F.);
#894=DIRECTION('',(0.866025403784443,-0.499999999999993,0.));
#895=VECTOR('',#894,1.);
#896=CARTESIAN_POINT('',(4.58012701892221,-2.06698729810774,7.5));
#897=LINE('',#896,#895);
#898=EDGE_CURVE('E628',#891,#184,#897,.T.);
#899=ORIENTED_EDGE('',*,*,#898,.T.);
#900=ORIENTED_EDGE('',*,*,#185,.T.);
#901=DIRECTION('',(-0.98480775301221,0.173648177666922,0.));
#902=VECTOR('',#901,1.);
#903=CARTESIAN_POINT('',(12.7156767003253,-2.74983018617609,7.5));
#904=LINE('',#903,#902);
#905=CARTESIAN_POINT('',(4.83721467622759,-1.36064476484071,7.5));
#906=VERTEX_POINT('',#905);
#907=EDGE_CURVE('E610',#180,#906,#904,.T.);
#908=ORIENTED_EDGE('',*,*,#907,.T.);
#909=DIRECTION('',(-0.173648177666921,-0.98480775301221,0.));
#910=VECTOR('',#909,1.);
#911=CARTESIAN_POINT('',(5.01086285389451,-0.375837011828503,7.5));
#912=LINE('',#911,#910);
#913=CARTESIAN_POINT('',(5.01086285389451,-0.375837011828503,7.5));
#914=VERTEX_POINT('',#913);
#915=EDGE_CURVE('E609',#914,#906,#912,.T.);
#916=ORIENTED_EDGE('',*,*,#915,.F.);
#917=DIRECTION('',(0.98480775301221,-0.173648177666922,0.));
#918=VECTOR('',#917,1.);
#919=CARTESIAN_POINT('',(5.01086285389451,-0.375837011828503,7.5));
#920=LINE('',#919,#918);
#921=EDGE_CURVE('E602',#914,#157,#920,.T.);
#922=ORIENTED_EDGE('',*,*,#921,.T.);
#923=ORIENTED_EDGE('',*,*,#158,.T.);
#924=DIRECTION('',(-0.984807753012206,-0.17364817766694,0.));
#925=VECTOR('',#924,1.);
#926=CARTESIAN_POINT('',(12.8893248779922,1.76502243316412,7.5));
#927=LINE('',#926,#925);
#928=CARTESIAN_POINT('',(5.0108628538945,0.375837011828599,7.5));
#929=VERTEX_POINT('',#928);
#930=EDGE_CURVE('E586',#153,#929,#927,.T.);
#931=ORIENTED_EDGE('',*,*,#930,.T.);
#932=DIRECTION('',(0.173648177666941,-0.984807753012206,0.));
#933=VECTOR('',#932,1.);
#934=CARTESIAN_POINT('',(4.83721467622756,1.36064476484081,7.5));
#935=LINE('',#934,#933);
#936=CARTESIAN_POINT('',(4.83721467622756,1.36064476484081,7.5));
#937=VERTEX_POINT('',#936);
#938=EDGE_CURVE('E588',#937,#929,#935,.T.);
#939=ORIENTED_EDGE('',*,*,#938,.F.);
#940=DIRECTION('',(0.984807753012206,0.17364817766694,0.));
#941=VECTOR('',#940,1.);
#942=CARTESIAN_POINT('',(4.83721467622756,1.36064476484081,7.5));
#943=LINE('',#942,#941);
#944=EDGE_CURVE('E583',#937,#130,#943,.T.);
#945=ORIENTED_EDGE('',*,*,#944,.T.);
#946=ORIENTED_EDGE('',*,*,#131,.T.);
#947=DIRECTION('',(-0.866025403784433,-0.500000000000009,0.));
#948=VECTOR('',#947,1.);
#949=CARTESIAN_POINT('',(11.5083302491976,6.0669872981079,7.5));
#950=LINE('',#949,#948);
#951=CARTESIAN_POINT('',(4.58012701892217,2.06698729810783,7.5));
#952=VERTEX_POINT('',#951);
#953=EDGE_CURVE('E558',#126,#952,#950,.T.);
#954=ORIENTED_EDGE('',*,*,#953,.T.);
#955=DIRECTION('',(0.50000000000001,-0.866025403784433,0.));
#956=VECTOR('',#955,1.);
#957=CARTESIAN_POINT('',(4.08012701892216,2.93301270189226,7.5));
#958=LINE('',#957,#956);
#959=CARTESIAN_POINT('',(4.08012701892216,2.93301270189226,7.5));
#960=VERTEX_POINT('',#959);
#961=EDGE_CURVE('E557',#960,#952,#958,.T.);
#962=ORIENTED_EDGE('',*,*,#961,.F.);
#963=DIRECTION('',(0.866025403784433,0.500000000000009,0.));
#964=VECTOR('',#963,1.);
#965=CARTESIAN_POINT('',(4.08012701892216,2.93301270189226,7.5));
#966=LINE('',#965,#964);
#967=EDGE_CURVE('E550',#960,#103,#966,.T.);
#968=ORIENTED_EDGE('',*,*,#967,.T.);
#969=ORIENTED_EDGE('',*,*,#104,.T.);
#970=DIRECTION('',(-0.642787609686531,-0.766044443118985,0.));
#971=VECTOR('',#970,1.);
#972=CARTESIAN_POINT('',(8.73926114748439,9.63718395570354,7.5));
#973=LINE('',#972,#971);
#974=CARTESIAN_POINT('',(3.59696026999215,3.50882841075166,7.5));
#975=VERTEX_POINT('',#974);
#976=EDGE_CURVE('E534',#99,#975,#973,.T.);
#977=ORIENTED_EDGE('',*,*,#976,.T.);
#978=DIRECTION('',(0.766044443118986,-0.64278760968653,0.));
#979=VECTOR('',#978,1.);
#980=CARTESIAN_POINT('',(2.83091582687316,4.15161602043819,7.5));
#981=LINE('',#980,#979);
#982=CARTESIAN_POINT('',(2.83091582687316,4.15161602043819,7.5));
#983=VERTEX_POINT('',#982);
#984=EDGE_CURVE('E533',#983,#975,#981,.T.);
#985=ORIENTED_EDGE('',*,*,#984,.F.);
#986=DIRECTION('',(0.642787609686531,0.766044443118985,0.));
#987=VECTOR('',#986,1.);
#988=CARTESIAN_POINT('',(2.83091582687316,4.15161602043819,7.5));
#989=LINE('',#988,#987);
#990=EDGE_CURVE('E526',#983,#76,#989,.T.);
#991=ORIENTED_EDGE('',*,*,#990,.T.);
#992=EDGE_LOOP('',(#573,#581,#589,#595,#596,#604,#612,#620,#624,#632,#640,#646,#647,#655,#663,
#669,#670,#678,#686,#692,#693,#701,#709,#715,#716,#724,#732,#738,#739,#747,#755,#761,#762,#770,
#778,#784,#785,#793,#801,#807,#808,#816,#824,#830,#831,#839,#847,#853,#854,#862,#870,#876,#877,
#885,#893,#899,#900,#908,#916,#922,#923,#931,#939,#945,#946,#954,#962,#968,#969,#977,#985,#991));
#993=FACE_BOUND('',#992,.T.);
#994=CARTESIAN_POINT('',(0.,0.,7.5));
#995=DIRECTION('',(0.,0.,1.));
#996=DIRECTION('',(1.,0.,0.));
#997=AXIS2_PLACEMENT_3D('',#994,#995,#996);
#998=CIRCLE('',#997,6.);
#999=CARTESIAN_POINT('',(6.,0.,7.5));
#1000=VERTEX_POINT('',#999);
#1001=EDGE_CURVE('E972',#1000,#1000,#998,.T.);
#1002=ORIENTED_EDGE('',*,*,#1001,.F.);
#1003=EDGE_LOOP('',(#1002));
#1004=FACE_BOUND('',#1003,.T.);
#1005=ADVANCED_FACE('F1008',(#993,#1004),#572,.F.);
#1006=CARTESIAN_POINT('',(0.,0.,8.5));
#1007=DIRECTION('',(0.,0.,-1.));
#1008=DIRECTION('',(-1.,0.,0.));
#1009=AXIS2_PLACEMENT_3D('',#1006,#1007,#1008);
#1010=CYLINDRICAL_SURFACE('',#1009,6.);
#1011=CARTESIAN_POINT('',(0.,0.,8.5));
#1012=DIRECTION('',(0.,0.,1.));
#1013=DIRECTION('',(1.,0.,0.));
#1014=AXIS2_PLACEMENT_3D('',#1011,#1012,#1013);
#1015=CIRCLE('',#1014,6.);
#1016=CARTESIAN_POINT('',(6.,0.,8.5));
#1017=VERTEX_POINT('',#1016);
#1018=EDGE_CURVE('E975',#1017,#1017,#1015,.T.);
#1019=ORIENTED_EDGE('',*,*,#1018,.F.);
#1020=EDGE_LOOP('',(#1019));
#1021=FACE_BOUND('',#1020,.T.);
#1022=ORIENTED_EDGE('',*,*,#1001,.T.);
#1023=EDGE_LOOP('',(#1022));
#1024=FACE_BOUND('',#1023,.T.);
#1025=ADVANCED_FACE('F1474',(#1021,#1024),#1010,.T.);
#1026=CARTESIAN_POINT('',(0.,0.,8.5));
#1027=DIRECTION('',(0.,0.,1.));
#1028=DIRECTION('',(1.,0.,0.));
#1029=AXIS2_PLACEMENT_3D('',#1026,#1027,#1028);
#1030=PLANE('',#1029);
#1031=ORIENTED_EDGE('',*,*,#515,.F.);
#1032=ORIENTED_EDGE('',*,*,#562,.T.);
#1033=EDGE_LOOP('',(#1031,#1032));
#1034=FACE_BOUND('',#1033,.T.);
#1035=ORIENTED_EDGE('',*,*,#1018,.T.);
#1036=EDGE_LOOP('',(#1035));
#1037=FACE_BOUND('',#1036,.T.);
#1038=ADVANCED_FACE('F1476',(#1034,#1037),#1030,.T.);
#1039=CARTESIAN_POINT('',(0.,0.,1.));
#1040=DIRECTION('',(0.,0.,1.));
#1041=DIRECTION('',(1.,0.,0.));
#1042=AXIS2_PLACEMENT_3D('',#1039,#1040,#1041);
#1043=PLANE('',#1042);
#1044=ORIENTED_EDGE('',*,*,#50,.F.);
#1045=DIRECTION('',(0.342020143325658,0.939692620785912,0.));
#1046=VECTOR('',#1045,1.);
#1047=CARTESIAN_POINT('',(1.24025440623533,4.86947317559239,1.));
#1048=LINE('',#1047,#1046);
#1049=CARTESIAN_POINT('',(1.24025440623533,4.86947317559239,1.));
#1050=VERTEX_POINT('',#1049);
#1051=EDGE_CURVE('E498',#1050,#40,#1048,.T.);
#1052=ORIENTED_EDGE('',*,*,#1051,.F.);
#1053=DIRECTION('',(0.939692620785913,-0.342020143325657,0.));
#1054=VECTOR('',#1053,1.);
#1055=CARTESIAN_POINT('',(1.24025440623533,4.86947317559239,1.));
#1056=LINE('',#1055,#1054);
#1057=CARTESIAN_POINT('',(2.17994702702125,4.52745303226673,1.));
#1058=VERTEX_POINT('',#1057);
#1059=EDGE_CURVE('E503',#1050,#1058,#1056,.T.);
#1060=ORIENTED_EDGE('',*,*,#1059,.T.);
#1061=DIRECTION('',(-0.342020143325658,-0.939692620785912,0.));
#1062=VECTOR('',#1061,1.);
#1063=CARTESIAN_POINT('',(4.91610817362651,12.044993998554,1.));
#1064=LINE('',#1063,#1062);
#1065=EDGE_CURVE('E45',#64,#1058,#1064,.T.);
#1066=ORIENTED_EDGE('',*,*,#1065,.F.);
#1067=ORIENTED_EDGE('',*,*,#65,.F.);
#1068=DIRECTION('',(0.642787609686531,0.766044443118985,0.));
#1069=VECTOR('',#1068,1.);
#1070=CARTESIAN_POINT('',(2.83091582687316,4.15161602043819,1.));
#1071=LINE('',#1070,#1069);
#1072=CARTESIAN_POINT('',(2.83091582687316,4.15161602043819,1.));
#1073=VERTEX_POINT('',#1072);
#1074=EDGE_CURVE('E537',#1073,#62,#1071,.T.);
#1075=ORIENTED_EDGE('',*,*,#1074,.F.);
#1076=DIRECTION('',(0.766044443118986,-0.64278760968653,0.));
#1077=VECTOR('',#1076,1.);
#1078=CARTESIAN_POINT('',(2.83091582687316,4.15161602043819,1.));
#1079=LINE('',#1078,#1077);
#1080=CARTESIAN_POINT('',(3.59696026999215,3.50882841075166,1.));
#1081=VERTEX_POINT('',#1080);
#1082=EDGE_CURVE('E529',#1073,#1081,#1079,.T.);
#1083=ORIENTED_EDGE('',*,*,#1082,.T.);
#1084=DIRECTION('',(-0.642787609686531,-0.766044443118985,0.));
#1085=VECTOR('',#1084,1.);
#1086=CARTESIAN_POINT('',(8.73926114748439,9.63718395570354,1.));
#1087=LINE('',#1086,#1085);
#1088=EDGE_CURVE('E52',#91,#1081,#1087,.T.);
#1089=ORIENTED_EDGE('',*,*,#1088,.F.);
#1090=ORIENTED_EDGE('',*,*,#92,.F.);
#1091=DIRECTION('',(0.866025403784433,0.500000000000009,0.));
#1092=VECTOR('',#1091,1.);
#1093=CARTESIAN_POINT('',(4.08012701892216,2.93301270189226,1.));
#1094=LINE('',#1093,#1092);
#1095=CARTESIAN_POINT('',(4.08012701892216,2.93301270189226,1.));
#1096=VERTEX_POINT('',#1095);
#1097=EDGE_CURVE('E561',#1096,#89,#1094,.T.);
#1098=ORIENTED_EDGE('',*,*,#1097,.F.);
#1099=DIRECTION('',(0.50000000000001,-0.866025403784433,0.));
#1100=VECTOR('',#1099,1.);
#1101=CARTESIAN_POINT('',(4.08012701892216,2.93301270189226,1.));
#1102=LINE('',#1101,#1100);
#1103=CARTESIAN_POINT('',(4.58012701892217,2.06698729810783,1.));
#1104=VERTEX_POINT('',#1103);
#1105=EDGE_CURVE('E553',#1096,#1104,#1102,.T.);
#1106=ORIENTED_EDGE('',*,*,#1105,.T.);
#1107=DIRECTION('',(-0.866025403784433,-0.500000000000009,0.));
#1108=VECTOR('',#1107,1.);
#1109=CARTESIAN_POINT('',(11.5083302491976,6.0669872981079,1.));
#1110=LINE('',#1109,#1108);
#1111=EDGE_CURVE('E567',#118,#1104,#1110,.T.);
#1112=ORIENTED_EDGE('',*,*,#1111,.F.);
#1113=ORIENTED_EDGE('',*,*,#119,.F.);
#1114=DIRECTION('',(0.984807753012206,0.17364817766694,0.));
#1115=VECTOR('',#1114,1.);
#1116=CARTESIAN_POINT('',(4.83721467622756,1.36064476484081,1.));
#1117=LINE('',#1116,#1115);
#1118=CARTESIAN_POINT('',(4.83721467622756,1.36064476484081,1.));
#1119=VERTEX_POINT('',#1118);
#1120=EDGE_CURVE('E576',#1119,#116,#1117,.T.);
#1121=ORIENTED_EDGE('',*,*,#1120,.F.);
#1122=DIRECTION('',(0.173648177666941,-0.984807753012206,0.));
#1123=VECTOR('',#1122,1.);
#1124=CARTESIAN_POINT('',(4.83721467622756,1.36064476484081,1.));
#1125=LINE('',#1124,#1123);
#1126=CARTESIAN_POINT('',(5.0108628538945,0.375837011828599,1.));
#1127=VERTEX_POINT('',#1126);
#1128=EDGE_CURVE('E580',#1119,#1127,#1125,.T.);
#1129=ORIENTED_EDGE('',*,*,#1128,.T.);
#1130=DIRECTION('',(-0.984807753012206,-0.17364817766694,0.));
#1131=VECTOR('',#1130,1.);
#1132=CARTESIAN_POINT('',(12.8893248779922,1.76502243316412,1.));
#1133=LINE('',#1132,#1131);
#1134=EDGE_CURVE('E578',#145,#1127,#1133,.T.);
#1135=ORIENTED_EDGE('',*,*,#1134,.F.);
#1136=ORIENTED_EDGE('',*,*,#146,.F.);
#1137=DIRECTION('',(0.98480775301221,-0.173648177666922,0.));
#1138=VECTOR('',#1137,1.);
#1139=CARTESIAN_POINT('',(5.01086285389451,-0.375837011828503,1.));
#1140=LINE('',#1139,#1138);
#1141=CARTESIAN_POINT('',(5.01086285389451,-0.375837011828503,1.));
#1142=VERTEX_POINT('',#1141);
#1143=EDGE_CURVE('E613',#1142,#143,#1140,.T.);
#1144=ORIENTED_EDGE('',*,*,#1143,.F.);
#1145=DIRECTION('',(-0.173648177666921,-0.98480775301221,0.));
#1146=VECTOR('',#1145,1.);
#1147=CARTESIAN_POINT('',(5.01086285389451,-0.375837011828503,1.));
#1148=LINE('',#1147,#1146);
#1149=CARTESIAN_POINT('',(4.83721467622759,-1.36064476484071,1.));
#1150=VERTEX_POINT('',#1149);
#1151=EDGE_CURVE('E605',#1142,#1150,#1148,.T.);
#1152=ORIENTED_EDGE('',*,*,#1151,.T.);
#1153=DIRECTION('',(-0.98480775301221,0.173648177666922,0.));
#1154=VECTOR('',#1153,1.);
#1155=CARTESIAN_POINT('',(12.7156767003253,-2.74983018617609,1.));
#1156=LINE('',#1155,#1154);
#1157=EDGE_CURVE('E619',#172,#1150,#1156,.T.);
#1158=ORIENTED_EDGE('',*,*,#1157,.F.);
#1159=ORIENTED_EDGE('',*,*,#173,.F.);
#1160=DIRECTION('',(0.866025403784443,-0.499999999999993,0.));
#1161=VECTOR('',#1160,1.);
#1162=CARTESIAN_POINT('',(4.58012701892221,-2.06698729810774,1.));
#1163=LINE('',#1162,#1161);
#1164=CARTESIAN_POINT('',(4.58012701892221,-2.06698729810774,1.));
#1165=VERTEX_POINT('',#1164);
#1166=EDGE_CURVE('E629',#1165,#170,#1163,.T.);
#1167=ORIENTED_EDGE('',*,*,#1166,.F.);
#1168=DIRECTION('',(-0.499999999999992,-0.866025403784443,0.));
#1169=VECTOR('',#1168,1.);
#1170=CARTESIAN_POINT('',(4.58012701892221,-2.06698729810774,1.));
#1171=LINE('',#1170,#1169);
#1172=CARTESIAN_POINT('',(4.08012701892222,-2.93301270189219,1.));
#1173=VERTEX_POINT('',#1172);
#1174=EDGE_CURVE('E635',#1165,#1173,#1171,.T.);
#1175=ORIENTED_EDGE('',*,*,#1174,.T.);
#1176=DIRECTION('',(-0.866025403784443,0.499999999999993,0.));
#1177=VECTOR('',#1176,1.);
#1178=CARTESIAN_POINT('',(11.0083302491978,-6.93301270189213,1.));
#1179=LINE('',#1178,#1177);
#1180=EDGE_CURVE('E631',#199,#1173,#1179,.T.);
#1181=ORIENTED_EDGE('',*,*,#1180,.F.);
#1182=ORIENTED_EDGE('',*,*,#200,.F.);
#1183=DIRECTION('',(0.642787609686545,-0.766044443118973,0.));
#1184=VECTOR('',#1183,1.);
#1185=CARTESIAN_POINT('',(3.59696026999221,-3.50882841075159,1.));
#1186=LINE('',#1185,#1184);
#1187=CARTESIAN_POINT('',(3.59696026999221,-3.50882841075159,1.));
#1188=VERTEX_POINT('',#1187);
#1189=EDGE_CURVE('E665',#1188,#197,#1186,.T.);
#1190=ORIENTED_EDGE('',*,*,#1189,.F.);
#1191=DIRECTION('',(-0.766044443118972,-0.642787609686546,0.));
#1192=VECTOR('',#1191,1.);
#1193=CARTESIAN_POINT('',(3.59696026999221,-3.50882841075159,1.));
#1194=LINE('',#1193,#1192);
#1195=CARTESIAN_POINT('',(2.83091582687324,-4.15161602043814,1.));
#1196=VERTEX_POINT('',#1195);
#1197=EDGE_CURVE('E657',#1188,#1196,#1194,.T.);
#1198=ORIENTED_EDGE('',*,*,#1197,.T.);
#1199=DIRECTION('',(-0.642787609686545,0.766044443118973,0.));
#1200=VECTOR('',#1199,1.);
#1201=CARTESIAN_POINT('',(7.9732167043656,-10.2799715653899,1.));
#1202=LINE('',#1201,#1200);
#1203=EDGE_CURVE('E671',#226,#1196,#1202,.T.);
#1204=ORIENTED_EDGE('',*,*,#1203,.F.);
#1205=ORIENTED_EDGE('',*,*,#227,.F.);
#1206=DIRECTION('',(0.342020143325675,-0.939692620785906,0.));
#1207=VECTOR('',#1206,1.);
#1208=CARTESIAN_POINT('',(2.17994702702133,-4.52745303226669,1.));
#1209=LINE('',#1208,#1207);
#1210=CARTESIAN_POINT('',(2.17994702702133,-4.52745303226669,1.));
#1211=VERTEX_POINT('',#1210);
#1212=EDGE_CURVE('E680',#1211,#224,#1209,.T.);
#1213=ORIENTED_EDGE('',*,*,#1212,.F.);
#1214=DIRECTION('',(-0.939692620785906,-0.342020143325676,0.));
#1215=VECTOR('',#1214,1.);
#1216=CARTESIAN_POINT('',(2.17994702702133,-4.52745303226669,1.));
#1217=LINE('',#1216,#1215);
#1218=CARTESIAN_POINT('',(1.24025440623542,-4.86947317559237,1.));
#1219=VERTEX_POINT('',#1218);
#1220=EDGE_CURVE('E684',#1211,#1219,#1217,.T.);
#1221=ORIENTED_EDGE('',*,*,#1220,.T.);
#1222=DIRECTION('',(-0.342020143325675,0.939692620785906,0.));
#1223=VECTOR('',#1222,1.);
#1224=CARTESIAN_POINT('',(3.97641555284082,-12.3870141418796,1.));
#1225=LINE('',#1224,#1223);
#1226=EDGE_CURVE('E682',#253,#1219,#1225,.T.);
#1227=ORIENTED_EDGE('',*,*,#1226,.F.);
#1228=ORIENTED_EDGE('',*,*,#254,.F.);
#1229=DIRECTION('',(0.,-1.,0.));
#1230=VECTOR('',#1229,1.);
#1231=CARTESIAN_POINT('',(0.500000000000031,-5.,1.));
#1232=LINE('',#1231,#1230);
#1233=CARTESIAN_POINT('',(0.500000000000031,-5.,1.));
#1234=VERTEX_POINT('',#1233);
#1235=EDGE_CURVE('E706',#1234,#251,#1232,.T.);
#1236=ORIENTED_EDGE('',*,*,#1235,.F.);
#1237=DIRECTION('',(-1.,0.,0.));
#1238=VECTOR('',#1237,1.);
#1239=CARTESIAN_POINT('',(0.500000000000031,-5.,1.));
#1240=LINE('',#1239,#1238);
#1241=CARTESIAN_POINT('',(-0.49999999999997,-5.,1.));
#1242=VERTEX_POINT('',#1241);
#1243=EDGE_CURVE('E710',#1234,#1242,#1240,.T.);
#1244=ORIENTED_EDGE('',*,*,#1243,.T.);
#1245=DIRECTION('',(0.,1.,0.));
#1246=VECTOR('',#1245,1.);
#1247=CARTESIAN_POINT('',(-0.499999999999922,-13.,1.));
#1248=LINE('',#1247,#1246);
#1249=EDGE_CURVE('E708',#280,#1242,#1248,.T.);
#1250=ORIENTED_EDGE('',*,*,#1249,.F.);
#1251=ORIENTED_EDGE('',*,*,#281,.F.);
#1252=DIRECTION('',(-0.342020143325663,-0.93969262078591,0.));
#1253=VECTOR('',#1252,1.);
#1254=CARTESIAN_POINT('',(-1.24025440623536,-4.86947317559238,1.));
#1255=LINE('',#1254,#1253);
#1256=CARTESIAN_POINT('',(-1.24025440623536,-4.86947317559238,1.));
#1257=VERTEX_POINT('',#1256);
#1258=EDGE_CURVE('E733',#1257,#278,#1255,.T.);
#1259=ORIENTED_EDGE('',*,*,#1258,.F.);
#1260=DIRECTION('',(-0.939692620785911,0.342020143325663,0.));
#1261=VECTOR('',#1260,1.);
#1262=CARTESIAN_POINT('',(-1.24025440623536,-4.86947317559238,1.));
#1263=LINE('',#1262,#1261);
#1264=CARTESIAN_POINT('',(-2.17994702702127,-4.52745303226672,1.));
#1265=VERTEX_POINT('',#1264);
#1266=EDGE_CURVE('E739',#1257,#1265,#1263,.T.);
#1267=ORIENTED_EDGE('',*,*,#1266,.T.);
#1268=DIRECTION('',(0.342020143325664,0.93969262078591,0.));
#1269=VECTOR('',#1268,1.);
#1270=CARTESIAN_POINT('',(-4.91610817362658,-12.044993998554,1.));
#1271=LINE('',#1270,#1269);
#1272=EDGE_CURVE('E735',#307,#1265,#1271,.T.);
#1273=ORIENTED_EDGE('',*,*,#1272,.F.);
#1274=ORIENTED_EDGE('',*,*,#308,.F.);
#1275=DIRECTION('',(-0.642787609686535,-0.766044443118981,0.));
#1276=VECTOR('',#1275,1.);
#1277=CARTESIAN_POINT('',(-2.83091582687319,-4.15161602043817,1.));
#1278=LINE('',#1277,#1276);
#1279=CARTESIAN_POINT('',(-2.83091582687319,-4.15161602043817,1.));
#1280=VERTEX_POINT('',#1279);
#1281=EDGE_CURVE('E769',#1280,#305,#1278,.T.);
#1282=ORIENTED_EDGE('',*,*,#1281,.F.);
#1283=DIRECTION('',(-0.766044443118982,0.642787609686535,0.));
#1284=VECTOR('',#1283,1.);
#1285=CARTESIAN_POINT('',(-2.83091582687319,-4.15161602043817,1.));
#1286=LINE('',#1285,#1284);
#1287=CARTESIAN_POINT('',(-3.59696026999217,-3.50882841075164,1.));
#1288=VERTEX_POINT('',#1287);
#1289=EDGE_CURVE('E761',#1280,#1288,#1286,.T.);
#1290=ORIENTED_EDGE('',*,*,#1289,.T.);
#1291=DIRECTION('',(0.642787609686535,0.766044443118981,0.));
#1292=VECTOR('',#1291,1.);
#1293=CARTESIAN_POINT('',(-8.73926114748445,-9.63718395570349,1.));
#1294=LINE('',#1293,#1292);
#1295=EDGE_CURVE('E775',#334,#1288,#1294,.T.);
#1296=ORIENTED_EDGE('',*,*,#1295,.F.);
#1297=ORIENTED_EDGE('',*,*,#335,.F.);
#1298=DIRECTION('',(-0.866025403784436,-0.500000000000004,0.));
#1299=VECTOR('',#1298,1.);
#1300=CARTESIAN_POINT('',(-4.08012701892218,-2.93301270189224,1.));
#1301=LINE('',#1300,#1299);
#1302=CARTESIAN_POINT('',(-4.08012701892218,-2.93301270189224,1.));
#1303=VERTEX_POINT('',#1302);
#1304=EDGE_CURVE('E795',#1303,#332,#1301,.T.);
#1305=ORIENTED_EDGE('',*,*,#1304,.F.);
#1306=DIRECTION('',(-0.500000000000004,0.866025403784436,0.));
#1307=VECTOR('',#1306,1.);
#1308=CARTESIAN_POINT('',(-4.08012701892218,-2.93301270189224,1.));
#1309=LINE('',#1308,#1307);
#1310=CARTESIAN_POINT('',(-4.58012701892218,-2.0669872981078,1.));
#1311=VERTEX_POINT('',#1310);
#1312=EDGE_CURVE('E787',#1303,#1311,#1309,.T.);
#1313=ORIENTED_EDGE('',*,*,#1312,.T.);
#1314=DIRECTION('',(0.866025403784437,0.500000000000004,0.));
#1315=VECTOR('',#1314,1.);
#1316=CARTESIAN_POINT('',(-11.5083302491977,-6.06698729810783,1.));
#1317=LINE('',#1316,#1315);
#1318=EDGE_CURVE('E801',#361,#1311,#1317,.T.);
#1319=ORIENTED_EDGE('',*,*,#1318,.F.);
#1320=ORIENTED_EDGE('',*,*,#362,.F.);
#1321=DIRECTION('',(-0.984807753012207,-0.173648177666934,0.));
#1322=VECTOR('',#1321,1.);
#1323=CARTESIAN_POINT('',(-4.83721467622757,-1.36064476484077,1.));
#1324=LINE('',#1323,#1322);
#1325=CARTESIAN_POINT('',(-4.83721467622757,-1.36064476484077,1.));
#1326=VERTEX_POINT('',#1325);
#1327=EDGE_CURVE('E810',#1326,#359,#1324,.T.);
#1328=ORIENTED_EDGE('',*,*,#1327,.F.);
#1329=DIRECTION('',(-0.173648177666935,0.984807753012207,0.));
#1330=VECTOR('',#1329,1.);
#1331=CARTESIAN_POINT('',(-4.83721467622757,-1.36064476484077,1.));
#1332=LINE('',#1331,#1330);
#1333=CARTESIAN_POINT('',(-5.0108628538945,-0.375837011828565,1.));
#1334=VERTEX_POINT('',#1333);
#1335=EDGE_CURVE('E814',#1326,#1334,#1332,.T.);
#1336=ORIENTED_EDGE('',*,*,#1335,.T.);
#1337=DIRECTION('',(0.984807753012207,0.173648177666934,0.));
#1338=VECTOR('',#1337,1.);
#1339=CARTESIAN_POINT('',(-12.8893248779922,-1.76502243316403,1.));
#1340=LINE('',#1339,#1338);
#1341=EDGE_CURVE('E812',#388,#1334,#1340,.T.);
#1342=ORIENTED_EDGE('',*,*,#1341,.F.);
#1343=ORIENTED_EDGE('',*,*,#389,.F.);
#1344=DIRECTION('',(-0.984807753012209,0.173648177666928,0.));
#1345=VECTOR('',#1344,1.);
#1346=CARTESIAN_POINT('',(-5.01086285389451,0.375837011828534,1.));
#1347=LINE('',#1346,#1345);
#1348=CARTESIAN_POINT('',(-5.01086285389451,0.375837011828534,1.));
#1349=VERTEX_POINT('',#1348);
#1350=EDGE_CURVE('E847',#1349,#386,#1347,.T.);
#1351=ORIENTED_EDGE('',*,*,#1350,.F.);
#1352=DIRECTION('',(0.173648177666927,0.984807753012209,0.));
#1353=VECTOR('',#1352,1.);
#1354=CARTESIAN_POINT('',(-5.01086285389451,0.375837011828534,1.));
#1355=LINE('',#1354,#1353);
#1356=CARTESIAN_POINT('',(-4.83721467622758,1.36064476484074,1.));
#1357=VERTEX_POINT('',#1356);
#1358=EDGE_CURVE('E839',#1349,#1357,#1355,.T.);
#1359=ORIENTED_EDGE('',*,*,#1358,.T.);
#1360=DIRECTION('',(0.984807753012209,-0.173648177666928,0.));
#1361=VECTOR('',#1360,1.);
#1362=CARTESIAN_POINT('',(-12.7156767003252,2.74983018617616,1.));
#1363=LINE('',#1362,#1361);
#1364=EDGE_CURVE('E853',#415,#1357,#1363,.T.);
#1365=ORIENTED_EDGE('',*,*,#1364,.F.);
#1366=ORIENTED_EDGE('',*,*,#416,.F.);
#1367=DIRECTION('',(-0.86602540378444,0.499999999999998,0.));
#1368=VECTOR('',#1367,1.);
#1369=CARTESIAN_POINT('',(-4.5801270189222,2.06698729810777,1.));
#1370=LINE('',#1369,#1368);
#1371=CARTESIAN_POINT('',(-4.5801270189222,2.06698729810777,1.));
#1372=VERTEX_POINT('',#1371);
#1373=EDGE_CURVE('E863',#1372,#413,#1370,.T.);
#1374=ORIENTED_EDGE('',*,*,#1373,.F.);
#1375=DIRECTION('',(0.499999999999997,0.86602540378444,0.));
#1376=VECTOR('',#1375,1.);
#1377=CARTESIAN_POINT('',(-4.5801270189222,2.06698729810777,1.));
#1378=LINE('',#1377,#1376);
#1379=CARTESIAN_POINT('',(-4.0801270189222,2.93301270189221,1.));
#1380=VERTEX_POINT('',#1379);
#1381=EDGE_CURVE('E869',#1372,#1380,#1378,.T.);
#1382=ORIENTED_EDGE('',*,*,#1381,.T.);
#1383=DIRECTION('',(0.86602540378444,-0.499999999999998,0.));
#1384=VECTOR('',#1383,1.);
#1385=CARTESIAN_POINT('',(-11.0083302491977,6.9330127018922,1.));
#1386=LINE('',#1385,#1384);
#1387=EDGE_CURVE('E865',#442,#1380,#1386,.T.);
#1388=ORIENTED_EDGE('',*,*,#1387,.F.);
#1389=ORIENTED_EDGE('',*,*,#443,.F.);
#1390=DIRECTION('',(-0.64278760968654,0.766044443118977,0.));
#1391=VECTOR('',#1390,1.);
#1392=CARTESIAN_POINT('',(-3.59696026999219,3.50882841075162,1.));
#1393=LINE('',#1392,#1391);
#1394=CARTESIAN_POINT('',(-3.59696026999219,3.50882841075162,1.));
#1395=VERTEX_POINT('',#1394);
#1396=EDGE_CURVE('E899',#1395,#440,#1393,.T.);
#1397=ORIENTED_EDGE('',*,*,#1396,.F.);
#1398=DIRECTION('',(0.766044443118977,0.642787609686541,0.));
#1399=VECTOR('',#1398,1.);
#1400=CARTESIAN_POINT('',(-3.59696026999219,3.50882841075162,1.));
#1401=LINE('',#1400,#1399);
#1402=CARTESIAN_POINT('',(-2.83091582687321,4.15161602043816,1.));
#1403=VERTEX_POINT('',#1402);
#1404=EDGE_CURVE('E891',#1395,#1403,#1401,.T.);
#1405=ORIENTED_EDGE('',*,*,#1404,.T.);
#1406=DIRECTION('',(0.64278760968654,-0.766044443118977,0.));
#1407=VECTOR('',#1406,1.);
#1408=CARTESIAN_POINT('',(-7.97321670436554,10.27997156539,1.));
#1409=LINE('',#1408,#1407);
#1410=EDGE_CURVE('E905',#469,#1403,#1409,.T.);
#1411=ORIENTED_EDGE('',*,*,#1410,.F.);
#1412=ORIENTED_EDGE('',*,*,#470,.F.);
#1413=DIRECTION('',(-0.342020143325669,0.939692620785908,0.));
#1414=VECTOR('',#1413,1.);
#1415=CARTESIAN_POINT('',(-2.1799470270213,4.52745303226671,1.));
#1416=LINE('',#1415,#1414);
#1417=CARTESIAN_POINT('',(-2.1799470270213,4.52745303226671,1.));
#1418=VERTEX_POINT('',#1417);
#1419=EDGE_CURVE('E914',#1418,#467,#1416,.T.);
#1420=ORIENTED_EDGE('',*,*,#1419,.F.);
#1421=DIRECTION('',(0.939692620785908,0.34202014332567,0.));
#1422=VECTOR('',#1421,1.);
#1423=CARTESIAN_POINT('',(-2.1799470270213,4.52745303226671,1.));
#1424=LINE('',#1423,#1422);
#1425=CARTESIAN_POINT('',(-1.24025440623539,4.86947317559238,1.));
#1426=VERTEX_POINT('',#1425);
#1427=EDGE_CURVE('E918',#1418,#1426,#1424,.T.);
#1428=ORIENTED_EDGE('',*,*,#1427,.T.);
#1429=DIRECTION('',(0.342020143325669,-0.939692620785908,0.));
#1430=VECTOR('',#1429,1.);
#1431=CARTESIAN_POINT('',(-3.97641555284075,12.3870141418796,1.));
#1432=LINE('',#1431,#1430);
#1433=CARTESIAN_POINT('',(-1.40347516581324,5.31791852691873,1.));
#1434=VERTEX_POINT('',#1433);
#1435=EDGE_CURVE('E916',#1434,#1426,#1432,.T.);
#1436=ORIENTED_EDGE('',*,*,#1435,.F.);
#1437=CARTESIAN_POINT('',(-0.5,5.47722557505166,1.));
#1438=VERTEX_POINT('',#1437);
#1439=EDGE_CURVE('E979',#1438,#1434,#47,.T.);
#1440=ORIENTED_EDGE('',*,*,#1439,.F.);
#1441=DIRECTION('',(0.,1.,0.));
#1442=VECTOR('',#1441,1.);
#1443=CARTESIAN_POINT('',(-0.5,5.,1.));
#1444=LINE('',#1443,#1442);
#1445=CARTESIAN_POINT('',(-0.5,5.,1.));
#1446=VERTEX_POINT('',#1445);
#1447=EDGE_CURVE('E934',#1446,#1438,#1444,.T.);
#1448=ORIENTED_EDGE('',*,*,#1447,.F.);
#1449=DIRECTION('',(1.,0.,0.));
#1450=VECTOR('',#1449,1.);
#1451=CARTESIAN_POINT('',(-0.5,5.,1.));
#1452=LINE('',#1451,#1450);
#1453=CARTESIAN_POINT('',(0.500000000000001,5.,1.));
#1454=VERTEX_POINT('',#1453);
#1455=EDGE_CURVE('E938',#1446,#1454,#1452,.T.);
#1456=ORIENTED_EDGE('',*,*,#1455,.T.);
#1457=DIRECTION('',(0.,-1.,0.));
#1458=VECTOR('',#1457,1.);
#1459=CARTESIAN_POINT('',(0.500000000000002,13.,1.));
#1460=LINE('',#1459,#1458);
#1461=EDGE_CURVE('E936',#49,#1454,#1460,.T.);
#1462=ORIENTED_EDGE('',*,*,#1461,.F.);
#1463=EDGE_LOOP('',(#1044,#1052,#1060,#1066,#1067,#1075,#1083,#1089,#1090,#1098,#1106,#1112,
#1113,#1121,#1129,#1135,#1136,#1144,#1152,#1158,#1159,#1167,#1175,#1181,#1182,#1190,#1198,#1204,
#1205,#1213,#1221,#1227,#1228,#1236,#1244,#1250,#1251,#1259,#1267,#1273,#1274,#1282,#1290,#1296,
#1297,#1305,#1313,#1319,#1320,#1328,#1336,#1342,#1343,#1351,#1359,#1365,#1366,#1374,#1382,#1388,
#1389,#1397,#1405,#1411,#1412,#1420,#1428,#1436,#1440,#1448,#1456,#1462));
#1464=FACE_BOUND('',#1463,.T.);
#1465=CARTESIAN_POINT('',(0.,0.,1.));
#1466=DIRECTION('',(0.,0.,1.));
#1467=DIRECTION('',(1.,0.,0.));
#1468=AXIS2_PLACEMENT_3D('',#1465,#1466,#1467);
#1469=CIRCLE('',#1468,6.);
#1470=CARTESIAN_POINT('',(6.,0.,1.));
#1471=VERTEX_POINT('',#1470);
#1472=EDGE_CURVE('E991',#1471,#1471,#1469,.T.);
#1473=ORIENTED_EDGE('',*,*,#1472,.T.);
#1474=EDGE_LOOP('',(#1473));
#1475=FACE_BOUND('',#1474,.T.);
#1476=ADVANCED_FACE('F510',(#1464,#1475),#1043,.T.);
#1477=CARTESIAN_POINT('',(0.,0.,1.));
#1478=DIRECTION('',(0.,0.,-1.));
#1479=DIRECTION('',(-1.,0.,0.));
#1480=AXIS2_PLACEMENT_3D('',#1477,#1478,#1479);
#1481=CYLINDRICAL_SURFACE('',#1480,6.);
#1482=ORIENTED_EDGE('',*,*,#1472,.F.);
#1483=EDGE_LOOP('',(#1482));
#1484=FACE_BOUND('',#1483,.T.);
#1485=CARTESIAN_POINT('',(0.,0.,0.));
#1486=DIRECTION('',(0.,0.,1.));
#1487=DIRECTION('',(1.,0.,0.));
#1488=AXIS2_PLACEMENT_3D('',#1485,#1486,#1487);
#1489=CIRCLE('',#1488,6.);
#1490=CARTESIAN_POINT('',(6.,0.,0.));
#1491=VERTEX_POINT('',#1490);
#1492=EDGE_CURVE('E987',#1491,#1491,#1489,.T.);
#1493=ORIENTED_EDGE('',*,*,#1492,.T.);
#1494=EDGE_LOOP('',(#1493));
#1495=FACE_BOUND('',#1494,.T.);
#1496=ADVANCED_FACE('F32',(#1484,#1495),#1481,.T.);
#1497=CARTESIAN_POINT('',(0.,0.,0.));
#1498=DIRECTION('',(0.,0.,1.));
#1499=DIRECTION('',(1.,0.,0.));
#1500=AXIS2_PLACEMENT_3D('',#1497,#1498,#1499);
#1501=PLANE('',#1500);
#1502=ORIENTED_EDGE('',*,*,#541,.F.);
#1503=EDGE_LOOP('',(#1502));
#1504=FACE_BOUND('',#1503,.T.);
#1505=ORIENTED_EDGE('',*,*,#1492,.F.);
#1506=EDGE_LOOP('',(#1505));
#1507=FACE_BOUND('',#1506,.T.);
#1508=ADVANCED_FACE('F1110',(#1504,#1507),#1501,.F.);
#1509=ORIENTED_EDGE('',*,*,#1439,.T.);
#1510=DIRECTION('',(0.,0.,-1.));
#1511=VECTOR('',#1510,1.);
#1512=CARTESIAN_POINT('',(-1.40347516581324,5.31791852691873,7.5));
#1513=LINE('',#1512,#1511);
#1514=EDGE_CURVE('E38',#1434,#622,#1513,.F.);
#1515=ORIENTED_EDGE('',*,*,#1514,.T.);
#1516=ORIENTED_EDGE('',*,*,#623,.F.);
#1517=DIRECTION('',(0.,0.,-1.));
#1518=VECTOR('',#1517,1.);
#1519=CARTESIAN_POINT('',(-0.5,5.47722557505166,7.5));
#1520=LINE('',#1519,#1518);
#1521=EDGE_CURVE('E997',#618,#1438,#1520,.T.);
#1522=ORIENTED_EDGE('',*,*,#1521,.T.);
#1523=EDGE_LOOP('',(#1509,#1515,#1516,#1522));
#1524=FACE_BOUND('',#1523,.T.);
#1525=ADVANCED_FACE('F1003',(#1524),#23,.T.);
#1526=CARTESIAN_POINT('',(0.,0.,3.5));
#1527=DIRECTION('',(0.,0.,-1.));
#1528=DIRECTION('',(-1.,0.,0.));
#1529=AXIS2_PLACEMENT_3D('',#1526,#1527,#1528);
#1530=PLANE('',#1529);
#1531=ORIENTED_EDGE('',*,*,#530,.T.);
#1532=ORIENTED_EDGE('',*,*,#555,.F.);
#1533=EDGE_LOOP('',(#1531,#1532));
#1534=FACE_BOUND('',#1533,.T.);
#1535=ADVANCED_FACE('F1109',(#1534),#1530,.T.);
#1536=CARTESIAN_POINT('',(-0.5,5.,7.5));
#1537=DIRECTION('',(-1.,0.,0.));
#1538=DIRECTION('',(0.,0.,1.));
#1539=AXIS2_PLACEMENT_3D('',#1536,#1537,#1538);
#1540=PLANE('',#1539);
#1541=ORIENTED_EDGE('',*,*,#619,.F.);
#1542=DIRECTION('',(0.,0.,-1.));
#1543=VECTOR('',#1542,1.);
#1544=CARTESIAN_POINT('',(-0.5,5.,7.5));
#1545=LINE('',#1544,#1543);
#1546=EDGE_CURVE('E952',#610,#1446,#1545,.T.);
#1547=ORIENTED_EDGE('',*,*,#1546,.T.);
#1548=ORIENTED_EDGE('',*,*,#1447,.T.);
#1549=ORIENTED_EDGE('',*,*,#1521,.F.);
#1550=EDGE_LOOP('',(#1541,#1547,#1548,#1549));
#1551=FACE_BOUND('',#1550,.T.);
#1552=ADVANCED_FACE('F1015',(#1551),#1540,.F.);
#1553=CARTESIAN_POINT('',(0.500000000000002,13.,7.5));
#1554=DIRECTION('',(1.,0.,0.));
#1555=DIRECTION('',(0.,1.,0.));
#1556=AXIS2_PLACEMENT_3D('',#1553,#1554,#1555);
#1557=PLANE('',#1556);
#1558=ORIENTED_EDGE('',*,*,#1461,.T.);
#1559=DIRECTION('',(0.,0.,-1.));
#1560=VECTOR('',#1559,1.);
#1561=CARTESIAN_POINT('',(0.500000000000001,5.,7.5));
#1562=LINE('',#1561,#1560);
#1563=EDGE_CURVE('E949',#602,#1454,#1562,.T.);
#1564=ORIENTED_EDGE('',*,*,#1563,.F.);
#1565=ORIENTED_EDGE('',*,*,#603,.F.);
#1566=ORIENTED_EDGE('',*,*,#56,.F.);
#1567=EDGE_LOOP('',(#1558,#1564,#1565,#1566));
#1568=FACE_BOUND('',#1567,.T.);
#1569=ADVANCED_FACE('F1083',(#1568),#1557,.F.);
#1570=CARTESIAN_POINT('',(-0.5,5.,7.5));
#1571=DIRECTION('',(0.,1.,0.));
#1572=DIRECTION('',(-1.,0.,0.));
#1573=AXIS2_PLACEMENT_3D('',#1570,#1571,#1572);
#1574=PLANE('',#1573);
#1575=ORIENTED_EDGE('',*,*,#1563,.T.);
#1576=ORIENTED_EDGE('',*,*,#1455,.F.);
#1577=ORIENTED_EDGE('',*,*,#1546,.F.);
#1578=ORIENTED_EDGE('',*,*,#611,.T.);
#1579=EDGE_LOOP('',(#1575,#1576,#1577,#1578));
#1580=FACE_BOUND('',#1579,.T.);
#1581=ADVANCED_FACE('F1087',(#1580),#1574,.T.);
#1582=CARTESIAN_POINT('',(-2.1799470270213,4.52745303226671,7.5));
#1583=DIRECTION('',(-0.939692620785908,-0.342020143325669,0.));
#1584=DIRECTION('',(0.342020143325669,-0.939692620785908,0.));
#1585=AXIS2_PLACEMENT_3D('',#1582,#1583,#1584);
#1586=PLANE('',#1585);
#1587=ORIENTED_EDGE('',*,*,#645,.F.);
#1588=DIRECTION('',(0.,0.,-1.));
#1589=VECTOR('',#1588,1.);
#1590=CARTESIAN_POINT('',(-2.1799470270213,4.52745303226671,7.5));
#1591=LINE('',#1590,#1589);
#1592=EDGE_CURVE('E932',#638,#1418,#1591,.T.);
#1593=ORIENTED_EDGE('',*,*,#1592,.T.);
#1594=ORIENTED_EDGE('',*,*,#1419,.T.);
#1595=ORIENTED_EDGE('',*,*,#488,.F.);
#1596=EDGE_LOOP('',(#1587,#1593,#1594,#1595));
#1597=FACE_BOUND('',#1596,.T.);
#1598=ADVANCED_FACE('F1089',(#1597),#1586,.F.);
#1599=CARTESIAN_POINT('',(-3.97641555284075,12.3870141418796,7.5));
#1600=DIRECTION('',(0.939692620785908,0.342020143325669,0.));
#1601=DIRECTION('',(-0.342020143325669,0.939692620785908,0.));
#1602=AXIS2_PLACEMENT_3D('',#1599,#1600,#1601);
#1603=PLANE('',#1602);
#1604=ORIENTED_EDGE('',*,*,#1435,.T.);
#1605=DIRECTION('',(0.,0.,-1.));
#1606=VECTOR('',#1605,1.);
#1607=CARTESIAN_POINT('',(-1.24025440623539,4.86947317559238,7.5));
#1608=LINE('',#1607,#1606);
#1609=EDGE_CURVE('E929',#630,#1426,#1608,.T.);
#1610=ORIENTED_EDGE('',*,*,#1609,.F.);
#1611=ORIENTED_EDGE('',*,*,#631,.F.);
#1612=ORIENTED_EDGE('',*,*,#1514,.F.);
#1613=EDGE_LOOP('',(#1604,#1610,#1611,#1612));
#1614=FACE_BOUND('',#1613,.T.);
#1615=ADVANCED_FACE('F1020',(#1614),#1603,.F.);
#1616=CARTESIAN_POINT('',(-2.1799470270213,4.52745303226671,7.5));
#1617=DIRECTION('',(-0.34202014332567,0.939692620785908,0.));
#1618=DIRECTION('',(-0.939692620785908,-0.34202014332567,0.));
#1619=AXIS2_PLACEMENT_3D('',#1616,#1617,#1618);
#1620=PLANE('',#1619);
#1621=ORIENTED_EDGE('',*,*,#1609,.T.);
#1622=ORIENTED_EDGE('',*,*,#1427,.F.);
#1623=ORIENTED_EDGE('',*,*,#1592,.F.);
#1624=ORIENTED_EDGE('',*,*,#639,.T.);
#1625=EDGE_LOOP('',(#1621,#1622,#1623,#1624));
#1626=FACE_BOUND('',#1625,.T.);
#1627=ADVANCED_FACE('F1022',(#1626),#1620,.T.);
#1628=CARTESIAN_POINT('',(-3.59696026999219,3.50882841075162,7.5));
#1629=DIRECTION('',(-0.766044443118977,-0.64278760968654,0.));
#1630=DIRECTION('',(0.64278760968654,-0.766044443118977,0.));
#1631=AXIS2_PLACEMENT_3D('',#1628,#1629,#1630);
#1632=PLANE('',#1631);
#1633=ORIENTED_EDGE('',*,*,#668,.F.);
#1634=DIRECTION('',(0.,0.,-1.));
#1635=VECTOR('',#1634,1.);
#1636=CARTESIAN_POINT('',(-3.59696026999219,3.50882841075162,7.5));
#1637=LINE('',#1636,#1635);
#1638=EDGE_CURVE('E889',#661,#1395,#1637,.T.);
#1639=ORIENTED_EDGE('',*,*,#1638,.T.);
#1640=ORIENTED_EDGE('',*,*,#1396,.T.);
#1641=ORIENTED_EDGE('',*,*,#461,.F.);
#1642=EDGE_LOOP('',(#1633,#1639,#1640,#1641));
#1643=FACE_BOUND('',#1642,.T.);
#1644=ADVANCED_FACE('F1361',(#1643),#1632,.F.);
#1645=CARTESIAN_POINT('',(-7.97321670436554,10.27997156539,7.5));
#1646=DIRECTION('',(0.766044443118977,0.64278760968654,0.));
#1647=DIRECTION('',(-0.64278760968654,0.766044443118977,0.));
#1648=AXIS2_PLACEMENT_3D('',#1645,#1646,#1647);
#1649=PLANE('',#1648);
#1650=ORIENTED_EDGE('',*,*,#1410,.T.);
#1651=DIRECTION('',(0.,0.,-1.));
#1652=VECTOR('',#1651,1.);
#1653=CARTESIAN_POINT('',(-2.83091582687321,4.15161602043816,7.5));
#1654=LINE('',#1653,#1652);
#1655=EDGE_CURVE('E892',#653,#1403,#1654,.T.);
#1656=ORIENTED_EDGE('',*,*,#1655,.F.);
#1657=ORIENTED_EDGE('',*,*,#654,.F.);
#1658=ORIENTED_EDGE('',*,*,#478,.F.);
#1659=EDGE_LOOP('',(#1650,#1656,#1657,#1658));
#1660=FACE_BOUND('',#1659,.T.);
#1661=ADVANCED_FACE('F1350',(#1660),#1649,.F.);
#1662=CARTESIAN_POINT('',(-3.59696026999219,3.50882841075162,7.5));
#1663=DIRECTION('',(-0.642787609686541,0.766044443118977,0.));
#1664=DIRECTION('',(-0.766044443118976,-0.642787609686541,0.));
#1665=AXIS2_PLACEMENT_3D('',#1662,#1663,#1664);
#1666=PLANE('',#1665);
#1667=ORIENTED_EDGE('',*,*,#1655,.T.);
#1668=ORIENTED_EDGE('',*,*,#1404,.F.);
#1669=ORIENTED_EDGE('',*,*,#1638,.F.);
#1670=ORIENTED_EDGE('',*,*,#662,.T.);
#1671=EDGE_LOOP('',(#1667,#1668,#1669,#1670));
#1672=FACE_BOUND('',#1671,.T.);
#1673=ADVANCED_FACE('F1343',(#1672),#1666,.T.);
#1674=CARTESIAN_POINT('',(-4.5801270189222,2.06698729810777,7.5));
#1675=DIRECTION('',(-0.499999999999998,-0.86602540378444,0.));
#1676=DIRECTION('',(0.86602540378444,-0.499999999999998,0.));
#1677=AXIS2_PLACEMENT_3D('',#1674,#1675,#1676);
#1678=PLANE('',#1677);
#1679=ORIENTED_EDGE('',*,*,#691,.F.);
#1680=DIRECTION('',(0.,0.,-1.));
#1681=VECTOR('',#1680,1.);
#1682=CARTESIAN_POINT('',(-4.5801270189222,2.06698729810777,7.5));
#1683=LINE('',#1682,#1681);
#1684=EDGE_CURVE('E873',#684,#1372,#1683,.T.);
#1685=ORIENTED_EDGE('',*,*,#1684,.T.);
#1686=ORIENTED_EDGE('',*,*,#1373,.T.);
#1687=ORIENTED_EDGE('',*,*,#434,.F.);
#1688=EDGE_LOOP('',(#1679,#1685,#1686,#1687));
#1689=FACE_BOUND('',#1688,.T.);
#1690=ADVANCED_FACE('F1341',(#1689),#1678,.F.);
#1691=CARTESIAN_POINT('',(-11.0083302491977,6.9330127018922,7.5));
#1692=DIRECTION('',(0.499999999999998,0.86602540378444,0.));
#1693=DIRECTION('',(-0.86602540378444,0.499999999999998,0.));
#1694=AXIS2_PLACEMENT_3D('',#1691,#1692,#1693);
#1695=PLANE('',#1694);
#1696=ORIENTED_EDGE('',*,*,#1387,.T.);
#1697=DIRECTION('',(0.,0.,-1.));
#1698=VECTOR('',#1697,1.);
#1699=CARTESIAN_POINT('',(-4.0801270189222,2.93301270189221,7.5));
#1700=LINE('',#1699,#1698);
#1701=EDGE_CURVE('E877',#676,#1380,#1700,.T.);
#1702=ORIENTED_EDGE('',*,*,#1701,.F.);
#1703=ORIENTED_EDGE('',*,*,#677,.F.);
#1704=ORIENTED_EDGE('',*,*,#451,.F.);
#1705=EDGE_LOOP('',(#1696,#1702,#1703,#1704));
#1706=FACE_BOUND('',#1705,.T.);
#1707=ADVANCED_FACE('F1340',(#1706),#1695,.F.);
#1708=CARTESIAN_POINT('',(-4.5801270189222,2.06698729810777,7.5));
#1709=DIRECTION('',(-0.86602540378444,0.499999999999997,0.));
#1710=DIRECTION('',(-0.499999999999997,-0.86602540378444,0.));
#1711=AXIS2_PLACEMENT_3D('',#1708,#1709,#1710);
#1712=PLANE('',#1711);
#1713=ORIENTED_EDGE('',*,*,#1701,.T.);
#1714=ORIENTED_EDGE('',*,*,#1381,.F.);
#1715=ORIENTED_EDGE('',*,*,#1684,.F.);
#1716=ORIENTED_EDGE('',*,*,#685,.T.);
#1717=EDGE_LOOP('',(#1713,#1714,#1715,#1716));
#1718=FACE_BOUND('',#1717,.T.);
#1719=ADVANCED_FACE('F1335',(#1718),#1712,.T.);
#1720=CARTESIAN_POINT('',(-5.01086285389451,0.375837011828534,7.5));
#1721=DIRECTION('',(-0.173648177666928,-0.984807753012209,0.));
#1722=DIRECTION('',(0.984807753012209,-0.173648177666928,0.));
#1723=AXIS2_PLACEMENT_3D('',#1720,#1721,#1722);
#1724=PLANE('',#1723);
#1725=ORIENTED_EDGE('',*,*,#714,.F.);
#1726=DIRECTION('',(0.,0.,-1.));
#1727=VECTOR('',#1726,1.);
#1728=CARTESIAN_POINT('',(-5.01086285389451,0.375837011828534,7.5));
#1729=LINE('',#1728,#1727);
#1730=EDGE_CURVE('E837',#707,#1349,#1729,.T.);
#1731=ORIENTED_EDGE('',*,*,#1730,.T.);
#1732=ORIENTED_EDGE('',*,*,#1350,.T.);
#1733=ORIENTED_EDGE('',*,*,#407,.F.);
#1734=EDGE_LOOP('',(#1725,#1731,#1732,#1733));
#1735=FACE_BOUND('',#1734,.T.);
#1736=ADVANCED_FACE('F1354',(#1735),#1724,.F.);
#1737=CARTESIAN_POINT('',(-12.7156767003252,2.74983018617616,7.5));
#1738=DIRECTION('',(0.173648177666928,0.984807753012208,0.));
#1739=DIRECTION('',(-0.984807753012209,0.173648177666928,0.));
#1740=AXIS2_PLACEMENT_3D('',#1737,#1738,#1739);
#1741=PLANE('',#1740);
#1742=ORIENTED_EDGE('',*,*,#1364,.T.);
#1743=DIRECTION('',(0.,0.,-1.));
#1744=VECTOR('',#1743,1.);
#1745=CARTESIAN_POINT('',(-4.83721467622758,1.36064476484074,7.5));
#1746=LINE('',#1745,#1744);
#1747=EDGE_CURVE('E840',#699,#1357,#1746,.T.);
#1748=ORIENTED_EDGE('',*,*,#1747,.F.);
#1749=ORIENTED_EDGE('',*,*,#700,.F.);
#1750=ORIENTED_EDGE('',*,*,#424,.F.);
#1751=EDGE_LOOP('',(#1742,#1748,#1749,#1750));
#1752=FACE_BOUND('',#1751,.T.);
#1753=ADVANCED_FACE('F1329',(#1752),#1741,.F.);
#1754=CARTESIAN_POINT('',(-5.01086285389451,0.375837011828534,7.5));
#1755=DIRECTION('',(-0.984807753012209,0.173648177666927,0.));
#1756=DIRECTION('',(-0.173648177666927,-0.984807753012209,0.));
#1757=AXIS2_PLACEMENT_3D('',#1754,#1755,#1756);
#1758=PLANE('',#1757);
#1759=ORIENTED_EDGE('',*,*,#1747,.T.);
#1760=ORIENTED_EDGE('',*,*,#1358,.F.);
#1761=ORIENTED_EDGE('',*,*,#1730,.F.);
#1762=ORIENTED_EDGE('',*,*,#708,.T.);
#1763=EDGE_LOOP('',(#1759,#1760,#1761,#1762));
#1764=FACE_BOUND('',#1763,.T.);
#1765=ADVANCED_FACE('F1324',(#1764),#1758,.T.);
#1766=CARTESIAN_POINT('',(-4.83721467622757,-1.36064476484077,7.5));
#1767=DIRECTION('',(0.173648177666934,-0.984807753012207,0.));
#1768=DIRECTION('',(0.984807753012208,0.173648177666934,0.));
#1769=AXIS2_PLACEMENT_3D('',#1766,#1767,#1768);
#1770=PLANE('',#1769);
#1771=ORIENTED_EDGE('',*,*,#737,.F.);
#1772=DIRECTION('',(0.,0.,-1.));
#1773=VECTOR('',#1772,1.);
#1774=CARTESIAN_POINT('',(-4.83721467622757,-1.36064476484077,7.5));
#1775=LINE('',#1774,#1773);
#1776=EDGE_CURVE('E828',#730,#1326,#1775,.T.);
#1777=ORIENTED_EDGE('',*,*,#1776,.T.);
#1778=ORIENTED_EDGE('',*,*,#1327,.T.);
#1779=ORIENTED_EDGE('',*,*,#380,.F.);
#1780=EDGE_LOOP('',(#1771,#1777,#1778,#1779));
#1781=FACE_BOUND('',#1780,.T.);
#1782=ADVANCED_FACE('F1637',(#1781),#1770,.F.);
#1783=CARTESIAN_POINT('',(-12.8893248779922,-1.76502243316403,7.5));
#1784=DIRECTION('',(-0.173648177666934,0.984807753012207,0.));
#1785=DIRECTION('',(-0.984807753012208,-0.173648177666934,0.));
#1786=AXIS2_PLACEMENT_3D('',#1783,#1784,#1785);
#1787=PLANE('',#1786);
#1788=ORIENTED_EDGE('',*,*,#1341,.T.);
#1789=DIRECTION('',(0.,0.,-1.));
#1790=VECTOR('',#1789,1.);
#1791=CARTESIAN_POINT('',(-5.0108628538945,-0.375837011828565,7.5));
#1792=LINE('',#1791,#1790);
#1793=EDGE_CURVE('E825',#722,#1334,#1792,.T.);
#1794=ORIENTED_EDGE('',*,*,#1793,.F.);
#1795=ORIENTED_EDGE('',*,*,#723,.F.);
#1796=ORIENTED_EDGE('',*,*,#397,.F.);
#1797=EDGE_LOOP('',(#1788,#1794,#1795,#1796));
#1798=FACE_BOUND('',#1797,.T.);
#1799=ADVANCED_FACE('F1318',(#1798),#1787,.F.);
#1800=CARTESIAN_POINT('',(-4.83721467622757,-1.36064476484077,7.5));
#1801=DIRECTION('',(-0.984807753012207,-0.173648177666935,0.));
#1802=DIRECTION('',(0.173648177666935,-0.984807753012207,0.));
#1803=AXIS2_PLACEMENT_3D('',#1800,#1801,#1802);
#1804=PLANE('',#1803);
#1805=ORIENTED_EDGE('',*,*,#1793,.T.);
#1806=ORIENTED_EDGE('',*,*,#1335,.F.);
#1807=ORIENTED_EDGE('',*,*,#1776,.F.);
#1808=ORIENTED_EDGE('',*,*,#731,.T.);
#1809=EDGE_LOOP('',(#1805,#1806,#1807,#1808));
#1810=FACE_BOUND('',#1809,.T.);
#1811=ADVANCED_FACE('F1313',(#1810),#1804,.T.);
#1812=CARTESIAN_POINT('',(-4.08012701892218,-2.93301270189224,7.5));
#1813=DIRECTION('',(0.500000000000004,-0.866025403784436,0.));
#1814=DIRECTION('',(0.866025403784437,0.500000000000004,0.));
#1815=AXIS2_PLACEMENT_3D('',#1812,#1813,#1814);
#1816=PLANE('',#1815);
#1817=ORIENTED_EDGE('',*,*,#760,.F.);
#1818=DIRECTION('',(0.,0.,-1.));
#1819=VECTOR('',#1818,1.);
#1820=CARTESIAN_POINT('',(-4.08012701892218,-2.93301270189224,7.5));
#1821=LINE('',#1820,#1819);
#1822=EDGE_CURVE('E785',#753,#1303,#1821,.T.);
#1823=ORIENTED_EDGE('',*,*,#1822,.T.);
#1824=ORIENTED_EDGE('',*,*,#1304,.T.);
#1825=ORIENTED_EDGE('',*,*,#353,.F.);
#1826=EDGE_LOOP('',(#1817,#1823,#1824,#1825));
#1827=FACE_BOUND('',#1826,.T.);
#1828=ADVANCED_FACE('F1656',(#1827),#1816,.F.);
#1829=CARTESIAN_POINT('',(-11.5083302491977,-6.06698729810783,7.5));
#1830=DIRECTION('',(-0.500000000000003,0.866025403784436,0.));
#1831=DIRECTION('',(-0.866025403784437,-0.500000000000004,0.));
#1832=AXIS2_PLACEMENT_3D('',#1829,#1830,#1831);
#1833=PLANE('',#1832);
#1834=ORIENTED_EDGE('',*,*,#1318,.T.);
#1835=DIRECTION('',(0.,0.,-1.));
#1836=VECTOR('',#1835,1.);
#1837=CARTESIAN_POINT('',(-4.58012701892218,-2.0669872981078,7.5));
#1838=LINE('',#1837,#1836);
#1839=EDGE_CURVE('E788',#745,#1311,#1838,.T.);
#1840=ORIENTED_EDGE('',*,*,#1839,.F.);
#1841=ORIENTED_EDGE('',*,*,#746,.F.);
#1842=ORIENTED_EDGE('',*,*,#370,.F.);
#1843=EDGE_LOOP('',(#1834,#1840,#1841,#1842));
#1844=FACE_BOUND('',#1843,.T.);
#1845=ADVANCED_FACE('F1307',(#1844),#1833,.F.);
#1846=CARTESIAN_POINT('',(-4.08012701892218,-2.93301270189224,7.5));
#1847=DIRECTION('',(-0.866025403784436,-0.500000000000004,0.));
#1848=DIRECTION('',(0.500000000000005,-0.866025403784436,0.));
#1849=AXIS2_PLACEMENT_3D('',#1846,#1847,#1848);
#1850=PLANE('',#1849);
#1851=ORIENTED_EDGE('',*,*,#1839,.T.);
#1852=ORIENTED_EDGE('',*,*,#1312,.F.);
#1853=ORIENTED_EDGE('',*,*,#1822,.F.);
#1854=ORIENTED_EDGE('',*,*,#754,.T.);
#1855=EDGE_LOOP('',(#1851,#1852,#1853,#1854));
#1856=FACE_BOUND('',#1855,.T.);
#1857=ADVANCED_FACE('F1302',(#1856),#1850,.T.);
#1858=CARTESIAN_POINT('',(-2.83091582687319,-4.15161602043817,7.5));
#1859=DIRECTION('',(0.766044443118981,-0.642787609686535,0.));
#1860=DIRECTION('',(0.642787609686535,0.766044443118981,0.));
#1861=AXIS2_PLACEMENT_3D('',#1858,#1859,#1860);
#1862=PLANE('',#1861);
#1863=ORIENTED_EDGE('',*,*,#783,.F.);
#1864=DIRECTION('',(0.,0.,-1.));
#1865=VECTOR('',#1864,1.);
#1866=CARTESIAN_POINT('',(-2.83091582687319,-4.15161602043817,7.5));
#1867=LINE('',#1866,#1865);
#1868=EDGE_CURVE('E759',#776,#1280,#1867,.T.);
#1869=ORIENTED_EDGE('',*,*,#1868,.T.);
#1870=ORIENTED_EDGE('',*,*,#1281,.T.);
#1871=ORIENTED_EDGE('',*,*,#326,.F.);
#1872=EDGE_LOOP('',(#1863,#1869,#1870,#1871));
#1873=FACE_BOUND('',#1872,.T.);
#1874=ADVANCED_FACE('F1675',(#1873),#1862,.F.);
#1875=CARTESIAN_POINT('',(-8.73926114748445,-9.63718395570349,7.5));
#1876=DIRECTION('',(-0.766044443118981,0.642787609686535,0.));
#1877=DIRECTION('',(-0.642787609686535,-0.766044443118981,0.));
#1878=AXIS2_PLACEMENT_3D('',#1875,#1876,#1877);
#1879=PLANE('',#1878);
#1880=ORIENTED_EDGE('',*,*,#1295,.T.);
#1881=DIRECTION('',(0.,0.,-1.));
#1882=VECTOR('',#1881,1.);
#1883=CARTESIAN_POINT('',(-3.59696026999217,-3.50882841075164,7.5));
#1884=LINE('',#1883,#1882);
#1885=EDGE_CURVE('E762',#768,#1288,#1884,.T.);
#1886=ORIENTED_EDGE('',*,*,#1885,.F.);
#1887=ORIENTED_EDGE('',*,*,#769,.F.);
#1888=ORIENTED_EDGE('',*,*,#343,.F.);
#1889=EDGE_LOOP('',(#1880,#1886,#1887,#1888));
#1890=FACE_BOUND('',#1889,.T.);
#1891=ADVANCED_FACE('F1296',(#1890),#1879,.F.);
#1892=CARTESIAN_POINT('',(-2.83091582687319,-4.15161602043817,7.5));
#1893=DIRECTION('',(-0.642787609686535,-0.766044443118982,0.));
#1894=DIRECTION('',(0.766044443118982,-0.642787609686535,0.));
#1895=AXIS2_PLACEMENT_3D('',#1892,#1893,#1894);
#1896=PLANE('',#1895);
#1897=ORIENTED_EDGE('',*,*,#1885,.T.);
#1898=ORIENTED_EDGE('',*,*,#1289,.F.);
#1899=ORIENTED_EDGE('',*,*,#1868,.F.);
#1900=ORIENTED_EDGE('',*,*,#777,.T.);
#1901=EDGE_LOOP('',(#1897,#1898,#1899,#1900));
#1902=FACE_BOUND('',#1901,.T.);
#1903=ADVANCED_FACE('F1291',(#1902),#1896,.T.);
#1904=CARTESIAN_POINT('',(-1.24025440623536,-4.86947317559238,7.5));
#1905=DIRECTION('',(0.93969262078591,-0.342020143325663,0.));
#1906=DIRECTION('',(0.342020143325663,0.93969262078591,0.));
#1907=AXIS2_PLACEMENT_3D('',#1904,#1905,#1906);
#1908=PLANE('',#1907);
#1909=ORIENTED_EDGE('',*,*,#806,.F.);
#1910=DIRECTION('',(0.,0.,-1.));
#1911=VECTOR('',#1910,1.);
#1912=CARTESIAN_POINT('',(-1.24025440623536,-4.86947317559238,7.5));
#1913=LINE('',#1912,#1911);
#1914=EDGE_CURVE('E743',#799,#1257,#1913,.T.);
#1915=ORIENTED_EDGE('',*,*,#1914,.T.);
#1916=ORIENTED_EDGE('',*,*,#1258,.T.);
#1917=ORIENTED_EDGE('',*,*,#299,.F.);
#1918=EDGE_LOOP('',(#1909,#1915,#1916,#1917));
#1919=FACE_BOUND('',#1918,.T.);
#1920=ADVANCED_FACE('F1694',(#1919),#1908,.F.);
#1921=CARTESIAN_POINT('',(-4.91610817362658,-12.044993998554,7.5));
#1922=DIRECTION('',(-0.93969262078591,0.342020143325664,0.));
#1923=DIRECTION('',(-0.342020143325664,-0.93969262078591,0.));
#1924=AXIS2_PLACEMENT_3D('',#1921,#1922,#1923);
#1925=PLANE('',#1924);
#1926=ORIENTED_EDGE('',*,*,#1272,.T.);
#1927=DIRECTION('',(0.,0.,-1.));
#1928=VECTOR('',#1927,1.);
#1929=CARTESIAN_POINT('',(-2.17994702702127,-4.52745303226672,7.5));
#1930=LINE('',#1929,#1928);
#1931=EDGE_CURVE('E747',#791,#1265,#1930,.T.);
#1932=ORIENTED_EDGE('',*,*,#1931,.F.);
#1933=ORIENTED_EDGE('',*,*,#792,.F.);
#1934=ORIENTED_EDGE('',*,*,#316,.F.);
#1935=EDGE_LOOP('',(#1926,#1932,#1933,#1934));
#1936=FACE_BOUND('',#1935,.T.);
#1937=ADVANCED_FACE('F1285',(#1936),#1925,.F.);
#1938=CARTESIAN_POINT('',(-1.24025440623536,-4.86947317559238,7.5));
#1939=DIRECTION('',(-0.342020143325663,-0.939692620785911,0.));
#1940=DIRECTION('',(0.939692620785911,-0.342020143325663,0.));
#1941=AXIS2_PLACEMENT_3D('',#1938,#1939,#1940);
#1942=PLANE('',#1941);
#1943=ORIENTED_EDGE('',*,*,#1931,.T.);
#1944=ORIENTED_EDGE('',*,*,#1266,.F.);
#1945=ORIENTED_EDGE('',*,*,#1914,.F.);
#1946=ORIENTED_EDGE('',*,*,#800,.T.);
#1947=EDGE_LOOP('',(#1943,#1944,#1945,#1946));
#1948=FACE_BOUND('',#1947,.T.);
#1949=ADVANCED_FACE('F1280',(#1948),#1942,.T.);
#1950=CARTESIAN_POINT('',(0.500000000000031,-5.,7.5));
#1951=DIRECTION('',(1.,0.,0.));
#1952=DIRECTION('',(0.,1.,0.));
#1953=AXIS2_PLACEMENT_3D('',#1950,#1951,#1952);
#1954=PLANE('',#1953);
#1955=ORIENTED_EDGE('',*,*,#829,.F.);
#1956=DIRECTION('',(0.,0.,-1.));
#1957=VECTOR('',#1956,1.);
#1958=CARTESIAN_POINT('',(0.500000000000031,-5.,7.5));
#1959=LINE('',#1958,#1957);
#1960=EDGE_CURVE('E724',#822,#1234,#1959,.T.);
#1961=ORIENTED_EDGE('',*,*,#1960,.T.);
#1962=ORIENTED_EDGE('',*,*,#1235,.T.);
#1963=ORIENTED_EDGE('',*,*,#272,.F.);
#1964=EDGE_LOOP('',(#1955,#1961,#1962,#1963));
#1965=FACE_BOUND('',#1964,.T.);
#1966=ADVANCED_FACE('F1713',(#1965),#1954,.F.);
#1967=CARTESIAN_POINT('',(-0.499999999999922,-13.,7.5));
#1968=DIRECTION('',(-1.,0.,0.));
#1969=DIRECTION('',(0.,-1.,0.));
#1970=AXIS2_PLACEMENT_3D('',#1967,#1968,#1969);
#1971=PLANE('',#1970);
#1972=ORIENTED_EDGE('',*,*,#1249,.T.);
#1973=DIRECTION('',(0.,0.,-1.));
#1974=VECTOR('',#1973,1.);
#1975=CARTESIAN_POINT('',(-0.49999999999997,-5.,7.5));
#1976=LINE('',#1975,#1974);
#1977=EDGE_CURVE('E721',#814,#1242,#1976,.T.);
#1978=ORIENTED_EDGE('',*,*,#1977,.F.);
#1979=ORIENTED_EDGE('',*,*,#815,.F.);
#1980=ORIENTED_EDGE('',*,*,#289,.F.);
#1981=EDGE_LOOP('',(#1972,#1978,#1979,#1980));
#1982=FACE_BOUND('',#1981,.T.);
#1983=ADVANCED_FACE('F1274',(#1982),#1971,.F.);
#1984=CARTESIAN_POINT('',(0.500000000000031,-5.,7.5));
#1985=DIRECTION('',(0.,-1.,0.));
#1986=DIRECTION('',(1.,0.,0.));
#1987=AXIS2_PLACEMENT_3D('',#1984,#1985,#1986);
#1988=PLANE('',#1987);
#1989=ORIENTED_EDGE('',*,*,#1977,.T.);
#1990=ORIENTED_EDGE('',*,*,#1243,.F.);
#1991=ORIENTED_EDGE('',*,*,#1960,.F.);
#1992=ORIENTED_EDGE('',*,*,#823,.T.);
#1993=EDGE_LOOP('',(#1989,#1990,#1991,#1992));
#1994=FACE_BOUND('',#1993,.T.);
#1995=ADVANCED_FACE('F1269',(#1994),#1988,.T.);
#1996=CARTESIAN_POINT('',(2.17994702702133,-4.52745303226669,7.5));
#1997=DIRECTION('',(0.939692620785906,0.342020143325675,0.));
#1998=DIRECTION('',(-0.342020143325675,0.939692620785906,0.));
#1999=AXIS2_PLACEMENT_3D('',#1996,#1997,#1998);
#2000=PLANE('',#1999);
#2001=ORIENTED_EDGE('',*,*,#852,.F.);
#2002=DIRECTION('',(0.,0.,-1.));
#2003=VECTOR('',#2002,1.);
#2004=CARTESIAN_POINT('',(2.17994702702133,-4.52745303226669,7.5));
#2005=LINE('',#2004,#2003);
#2006=EDGE_CURVE('E698',#845,#1211,#2005,.T.);
#2007=ORIENTED_EDGE('',*,*,#2006,.T.);
#2008=ORIENTED_EDGE('',*,*,#1212,.T.);
#2009=ORIENTED_EDGE('',*,*,#245,.F.);
#2010=EDGE_LOOP('',(#2001,#2007,#2008,#2009));
#2011=FACE_BOUND('',#2010,.T.);
#2012=ADVANCED_FACE('F1732',(#2011),#2000,.F.);
#2013=CARTESIAN_POINT('',(3.97641555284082,-12.3870141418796,7.5));
#2014=DIRECTION('',(-0.939692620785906,-0.342020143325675,0.));
#2015=DIRECTION('',(0.342020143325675,-0.939692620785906,0.));
#2016=AXIS2_PLACEMENT_3D('',#2013,#2014,#2015);
#2017=PLANE('',#2016);
#2018=ORIENTED_EDGE('',*,*,#1226,.T.);
#2019=DIRECTION('',(0.,0.,-1.));
#2020=VECTOR('',#2019,1.);
#2021=CARTESIAN_POINT('',(1.24025440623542,-4.86947317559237,7.5));
#2022=LINE('',#2021,#2020);
#2023=EDGE_CURVE('E695',#837,#1219,#2022,.T.);
#2024=ORIENTED_EDGE('',*,*,#2023,.F.);
#2025=ORIENTED_EDGE('',*,*,#838,.F.);
#2026=ORIENTED_EDGE('',*,*,#262,.F.);
#2027=EDGE_LOOP('',(#2018,#2024,#2025,#2026));
#2028=FACE_BOUND('',#2027,.T.);
#2029=ADVANCED_FACE('F1263',(#2028),#2017,.F.);
#2030=CARTESIAN_POINT('',(2.17994702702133,-4.52745303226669,7.5));
#2031=DIRECTION('',(0.342020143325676,-0.939692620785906,0.));
#2032=DIRECTION('',(0.939692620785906,0.342020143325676,0.));
#2033=AXIS2_PLACEMENT_3D('',#2030,#2031,#2032);
#2034=PLANE('',#2033);
#2035=ORIENTED_EDGE('',*,*,#2023,.T.);
#2036=ORIENTED_EDGE('',*,*,#1220,.F.);
#2037=ORIENTED_EDGE('',*,*,#2006,.F.);
#2038=ORIENTED_EDGE('',*,*,#846,.T.);
#2039=EDGE_LOOP('',(#2035,#2036,#2037,#2038));
#2040=FACE_BOUND('',#2039,.T.);
#2041=ADVANCED_FACE('F1258',(#2040),#2034,.T.);
#2042=CARTESIAN_POINT('',(3.59696026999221,-3.50882841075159,7.5));
#2043=DIRECTION('',(0.766044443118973,0.642787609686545,0.));
#2044=DIRECTION('',(-0.642787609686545,0.766044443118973,0.));
#2045=AXIS2_PLACEMENT_3D('',#2042,#2043,#2044);
#2046=PLANE('',#2045);
#2047=ORIENTED_EDGE('',*,*,#875,.F.);
#2048=DIRECTION('',(0.,0.,-1.));
#2049=VECTOR('',#2048,1.);
#2050=CARTESIAN_POINT('',(3.59696026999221,-3.50882841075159,7.5));
#2051=LINE('',#2050,#2049);
#2052=EDGE_CURVE('E655',#868,#1188,#2051,.T.);
#2053=ORIENTED_EDGE('',*,*,#2052,.T.);
#2054=ORIENTED_EDGE('',*,*,#1189,.T.);
#2055=ORIENTED_EDGE('',*,*,#218,.F.);
#2056=EDGE_LOOP('',(#2047,#2053,#2054,#2055));
#2057=FACE_BOUND('',#2056,.T.);
#2058=ADVANCED_FACE('F1751',(#2057),#2046,.F.);
#2059=CARTESIAN_POINT('',(7.9732167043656,-10.2799715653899,7.5));
#2060=DIRECTION('',(-0.766044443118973,-0.642787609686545,0.));
#2061=DIRECTION('',(0.642787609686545,-0.766044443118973,0.));
#2062=AXIS2_PLACEMENT_3D('',#2059,#2060,#2061);
#2063=PLANE('',#2062);
#2064=ORIENTED_EDGE('',*,*,#1203,.T.);
#2065=DIRECTION('',(0.,0.,-1.));
#2066=VECTOR('',#2065,1.);
#2067=CARTESIAN_POINT('',(2.83091582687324,-4.15161602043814,7.5));
#2068=LINE('',#2067,#2066);
#2069=EDGE_CURVE('E658',#860,#1196,#2068,.T.);
#2070=ORIENTED_EDGE('',*,*,#2069,.F.);
#2071=ORIENTED_EDGE('',*,*,#861,.F.);
#2072=ORIENTED_EDGE('',*,*,#235,.F.);
#2073=EDGE_LOOP('',(#2064,#2070,#2071,#2072));
#2074=FACE_BOUND('',#2073,.T.);
#2075=ADVANCED_FACE('F1252',(#2074),#2063,.F.);
#2076=CARTESIAN_POINT('',(3.59696026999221,-3.50882841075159,7.5));
#2077=DIRECTION('',(0.642787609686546,-0.766044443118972,0.));
#2078=DIRECTION('',(0.766044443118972,0.642787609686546,0.));
#2079=AXIS2_PLACEMENT_3D('',#2076,#2077,#2078);
#2080=PLANE('',#2079);
#2081=ORIENTED_EDGE('',*,*,#2069,.T.);
#2082=ORIENTED_EDGE('',*,*,#1197,.F.);
#2083=ORIENTED_EDGE('',*,*,#2052,.F.);
#2084=ORIENTED_EDGE('',*,*,#869,.T.);
#2085=EDGE_LOOP('',(#2081,#2082,#2083,#2084));
#2086=FACE_BOUND('',#2085,.T.);
#2087=ADVANCED_FACE('F1247',(#2086),#2080,.T.);
#2088=CARTESIAN_POINT('',(4.58012701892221,-2.06698729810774,7.5));
#2089=DIRECTION('',(0.499999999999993,0.866025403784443,0.));
#2090=DIRECTION('',(-0.866025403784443,0.499999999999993,0.));
#2091=AXIS2_PLACEMENT_3D('',#2088,#2089,#2090);
#2092=PLANE('',#2091);
#2093=ORIENTED_EDGE('',*,*,#898,.F.);
#2094=DIRECTION('',(0.,0.,-1.));
#2095=VECTOR('',#2094,1.);
#2096=CARTESIAN_POINT('',(4.58012701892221,-2.06698729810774,7.5));
#2097=LINE('',#2096,#2095);
#2098=EDGE_CURVE('E639',#891,#1165,#2097,.T.);
#2099=ORIENTED_EDGE('',*,*,#2098,.T.);
#2100=ORIENTED_EDGE('',*,*,#1166,.T.);
#2101=ORIENTED_EDGE('',*,*,#191,.F.);
#2102=EDGE_LOOP('',(#2093,#2099,#2100,#2101));
#2103=FACE_BOUND('',#2102,.T.);
#2104=ADVANCED_FACE('F1770',(#2103),#2092,.F.);
#2105=CARTESIAN_POINT('',(11.0083302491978,-6.93301270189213,7.5));
#2106=DIRECTION('',(-0.499999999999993,-0.866025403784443,0.));
#2107=DIRECTION('',(0.866025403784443,-0.499999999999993,0.));
#2108=AXIS2_PLACEMENT_3D('',#2105,#2106,#2107);
#2109=PLANE('',#2108);
#2110=ORIENTED_EDGE('',*,*,#1180,.T.);
#2111=DIRECTION('',(0.,0.,-1.));
#2112=VECTOR('',#2111,1.);
#2113=CARTESIAN_POINT('',(4.08012701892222,-2.93301270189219,7.5));
#2114=LINE('',#2113,#2112);
#2115=EDGE_CURVE('E643',#883,#1173,#2114,.T.);
#2116=ORIENTED_EDGE('',*,*,#2115,.F.);
#2117=ORIENTED_EDGE('',*,*,#884,.F.);
#2118=ORIENTED_EDGE('',*,*,#208,.F.);
#2119=EDGE_LOOP('',(#2110,#2116,#2117,#2118));
#2120=FACE_BOUND('',#2119,.T.);
#2121=ADVANCED_FACE('F1241',(#2120),#2109,.F.);
#2122=CARTESIAN_POINT('',(4.58012701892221,-2.06698729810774,7.5));
#2123=DIRECTION('',(0.866025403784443,-0.499999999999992,0.));
#2124=DIRECTION('',(0.499999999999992,0.866025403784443,0.));
#2125=AXIS2_PLACEMENT_3D('',#2122,#2123,#2124);
#2126=PLANE('',#2125);
#2127=ORIENTED_EDGE('',*,*,#2115,.T.);
#2128=ORIENTED_EDGE('',*,*,#1174,.F.);
#2129=ORIENTED_EDGE('',*,*,#2098,.F.);
#2130=ORIENTED_EDGE('',*,*,#892,.T.);
#2131=EDGE_LOOP('',(#2127,#2128,#2129,#2130));
#2132=FACE_BOUND('',#2131,.T.);
#2133=ADVANCED_FACE('F1236',(#2132),#2126,.T.);
#2134=CARTESIAN_POINT('',(5.01086285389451,-0.375837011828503,7.5));
#2135=DIRECTION('',(0.173648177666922,0.98480775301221,0.));
#2136=DIRECTION('',(-0.98480775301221,0.173648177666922,0.));
#2137=AXIS2_PLACEMENT_3D('',#2134,#2135,#2136);
#2138=PLANE('',#2137);
#2139=ORIENTED_EDGE('',*,*,#921,.F.);
#2140=DIRECTION('',(0.,0.,-1.));
#2141=VECTOR('',#2140,1.);
#2142=CARTESIAN_POINT('',(5.01086285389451,-0.375837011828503,7.5));
#2143=LINE('',#2142,#2141);
#2144=EDGE_CURVE('E603',#914,#1142,#2143,.T.);
#2145=ORIENTED_EDGE('',*,*,#2144,.T.);
#2146=ORIENTED_EDGE('',*,*,#1143,.T.);
#2147=ORIENTED_EDGE('',*,*,#164,.F.);
#2148=EDGE_LOOP('',(#2139,#2145,#2146,#2147));
#2149=FACE_BOUND('',#2148,.T.);
#2150=ADVANCED_FACE('F1789',(#2149),#2138,.F.);
#2151=CARTESIAN_POINT('',(12.7156767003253,-2.74983018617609,7.5));
#2152=DIRECTION('',(-0.173648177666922,-0.984807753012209,0.));
#2153=DIRECTION('',(0.98480775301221,-0.173648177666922,0.));
#2154=AXIS2_PLACEMENT_3D('',#2151,#2152,#2153);
#2155=PLANE('',#2154);
#2156=ORIENTED_EDGE('',*,*,#1157,.T.);
#2157=DIRECTION('',(0.,0.,-1.));
#2158=VECTOR('',#2157,1.);
#2159=CARTESIAN_POINT('',(4.83721467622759,-1.36064476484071,7.5));
#2160=LINE('',#2159,#2158);
#2161=EDGE_CURVE('E606',#906,#1150,#2160,.T.);
#2162=ORIENTED_EDGE('',*,*,#2161,.F.);
#2163=ORIENTED_EDGE('',*,*,#907,.F.);
#2164=ORIENTED_EDGE('',*,*,#181,.F.);
#2165=EDGE_LOOP('',(#2156,#2162,#2163,#2164));
#2166=FACE_BOUND('',#2165,.T.);
#2167=ADVANCED_FACE('F1230',(#2166),#2155,.F.);
#2168=CARTESIAN_POINT('',(5.01086285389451,-0.375837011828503,7.5));
#2169=DIRECTION('',(0.98480775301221,-0.173648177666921,0.));
#2170=DIRECTION('',(0.173648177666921,0.98480775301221,0.));
#2171=AXIS2_PLACEMENT_3D('',#2168,#2169,#2170);
#2172=PLANE('',#2171);
#2173=ORIENTED_EDGE('',*,*,#2161,.T.);
#2174=ORIENTED_EDGE('',*,*,#1151,.F.);
#2175=ORIENTED_EDGE('',*,*,#2144,.F.);
#2176=ORIENTED_EDGE('',*,*,#915,.T.);
#2177=EDGE_LOOP('',(#2173,#2174,#2175,#2176));
#2178=FACE_BOUND('',#2177,.T.);
#2179=ADVANCED_FACE('F1225',(#2178),#2172,.T.);
#2180=CARTESIAN_POINT('',(4.83721467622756,1.36064476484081,7.5));
#2181=DIRECTION('',(-0.17364817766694,0.984807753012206,0.));
#2182=DIRECTION('',(-0.984807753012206,-0.17364817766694,0.));
#2183=AXIS2_PLACEMENT_3D('',#2180,#2181,#2182);
#2184=PLANE('',#2183);
#2185=ORIENTED_EDGE('',*,*,#944,.F.);
#2186=DIRECTION('',(0.,0.,-1.));
#2187=VECTOR('',#2186,1.);
#2188=CARTESIAN_POINT('',(4.83721467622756,1.36064476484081,7.5));
#2189=LINE('',#2188,#2187);
#2190=EDGE_CURVE('E594',#937,#1119,#2189,.T.);
#2191=ORIENTED_EDGE('',*,*,#2190,.T.);
#2192=ORIENTED_EDGE('',*,*,#1120,.T.);
#2193=ORIENTED_EDGE('',*,*,#137,.F.);
#2194=EDGE_LOOP('',(#2185,#2191,#2192,#2193));
#2195=FACE_BOUND('',#2194,.T.);
#2196=ADVANCED_FACE('F1808',(#2195),#2184,.F.);
#2197=CARTESIAN_POINT('',(12.8893248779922,1.76502243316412,7.5));
#2198=DIRECTION('',(0.17364817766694,-0.984807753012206,0.));
#2199=DIRECTION('',(0.984807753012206,0.17364817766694,0.));
#2200=AXIS2_PLACEMENT_3D('',#2197,#2198,#2199);
#2201=PLANE('',#2200);
#2202=ORIENTED_EDGE('',*,*,#1134,.T.);
#2203=DIRECTION('',(0.,0.,-1.));
#2204=VECTOR('',#2203,1.);
#2205=CARTESIAN_POINT('',(5.0108628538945,0.375837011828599,7.5));
#2206=LINE('',#2205,#2204);
#2207=EDGE_CURVE('E591',#929,#1127,#2206,.T.);
#2208=ORIENTED_EDGE('',*,*,#2207,.F.);
#2209=ORIENTED_EDGE('',*,*,#930,.F.);
#2210=ORIENTED_EDGE('',*,*,#154,.F.);
#2211=EDGE_LOOP('',(#2202,#2208,#2209,#2210));
#2212=FACE_BOUND('',#2211,.T.);
#2213=ADVANCED_FACE('F1219',(#2212),#2201,.F.);
#2214=CARTESIAN_POINT('',(4.83721467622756,1.36064476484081,7.5));
#2215=DIRECTION('',(0.984807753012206,0.173648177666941,0.));
#2216=DIRECTION('',(-0.173648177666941,0.984807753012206,0.));
#2217=AXIS2_PLACEMENT_3D('',#2214,#2215,#2216);
#2218=PLANE('',#2217);
#2219=ORIENTED_EDGE('',*,*,#2207,.T.);
#2220=ORIENTED_EDGE('',*,*,#1128,.F.);
#2221=ORIENTED_EDGE('',*,*,#2190,.F.);
#2222=ORIENTED_EDGE('',*,*,#938,.T.);
#2223=EDGE_LOOP('',(#2219,#2220,#2221,#2222));
#2224=FACE_BOUND('',#2223,.T.);
#2225=ADVANCED_FACE('F1214',(#2224),#2218,.T.);
#2226=CARTESIAN_POINT('',(4.08012701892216,2.93301270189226,7.5));
#2227=DIRECTION('',(-0.500000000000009,0.866025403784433,0.));
#2228=DIRECTION('',(-0.866025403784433,-0.500000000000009,0.));
#2229=AXIS2_PLACEMENT_3D('',#2226,#2227,#2228);
#2230=PLANE('',#2229);
#2231=ORIENTED_EDGE('',*,*,#967,.F.);
#2232=DIRECTION('',(0.,0.,-1.));
#2233=VECTOR('',#2232,1.);
#2234=CARTESIAN_POINT('',(4.08012701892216,2.93301270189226,7.5));
#2235=LINE('',#2234,#2233);
#2236=EDGE_CURVE('E551',#960,#1096,#2235,.T.);
#2237=ORIENTED_EDGE('',*,*,#2236,.T.);
#2238=ORIENTED_EDGE('',*,*,#1097,.T.);
#2239=ORIENTED_EDGE('',*,*,#110,.F.);
#2240=EDGE_LOOP('',(#2231,#2237,#2238,#2239));
#2241=FACE_BOUND('',#2240,.T.);
#2242=ADVANCED_FACE('F1827',(#2241),#2230,.F.);
#2243=CARTESIAN_POINT('',(11.5083302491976,6.0669872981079,7.5));
#2244=DIRECTION('',(0.500000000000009,-0.866025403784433,0.));
#2245=DIRECTION('',(0.866025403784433,0.500000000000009,0.));
#2246=AXIS2_PLACEMENT_3D('',#2243,#2244,#2245);
#2247=PLANE('',#2246);
#2248=ORIENTED_EDGE('',*,*,#1111,.T.);
#2249=DIRECTION('',(0.,0.,-1.));
#2250=VECTOR('',#2249,1.);
#2251=CARTESIAN_POINT('',(4.58012701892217,2.06698729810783,7.5));
#2252=LINE('',#2251,#2250);
#2253=EDGE_CURVE('E554',#952,#1104,#2252,.T.);
#2254=ORIENTED_EDGE('',*,*,#2253,.F.);
#2255=ORIENTED_EDGE('',*,*,#953,.F.);
#2256=ORIENTED_EDGE('',*,*,#127,.F.);
#2257=EDGE_LOOP('',(#2248,#2254,#2255,#2256));
#2258=FACE_BOUND('',#2257,.T.);
#2259=ADVANCED_FACE('F1208',(#2258),#2247,.F.);
#2260=CARTESIAN_POINT('',(4.08012701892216,2.93301270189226,7.5));
#2261=DIRECTION('',(0.866025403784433,0.50000000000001,0.));
#2262=DIRECTION('',(-0.50000000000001,0.866025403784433,0.));
#2263=AXIS2_PLACEMENT_3D('',#2260,#2261,#2262);
#2264=PLANE('',#2263);
#2265=ORIENTED_EDGE('',*,*,#2253,.T.);
#2266=ORIENTED_EDGE('',*,*,#1105,.F.);
#2267=ORIENTED_EDGE('',*,*,#2236,.F.);
#2268=ORIENTED_EDGE('',*,*,#961,.T.);
#2269=EDGE_LOOP('',(#2265,#2266,#2267,#2268));
#2270=FACE_BOUND('',#2269,.T.);
#2271=ADVANCED_FACE('F1204',(#2270),#2264,.T.);
#2272=CARTESIAN_POINT('',(2.83091582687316,4.15161602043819,7.5));
#2273=DIRECTION('',(-0.766044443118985,0.642787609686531,0.));
#2274=DIRECTION('',(-0.642787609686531,-0.766044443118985,0.));
#2275=AXIS2_PLACEMENT_3D('',#2272,#2273,#2274);
#2276=PLANE('',#2275);
#2277=ORIENTED_EDGE('',*,*,#990,.F.);
#2278=DIRECTION('',(0.,0.,-1.));
#2279=VECTOR('',#2278,1.);
#2280=CARTESIAN_POINT('',(2.83091582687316,4.15161602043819,7.5));
#2281=LINE('',#2280,#2279);
#2282=EDGE_CURVE('E527',#983,#1073,#2281,.T.);
#2283=ORIENTED_EDGE('',*,*,#2282,.T.);
#2284=ORIENTED_EDGE('',*,*,#1074,.T.);
#2285=ORIENTED_EDGE('',*,*,#83,.F.);
#2286=EDGE_LOOP('',(#2277,#2283,#2284,#2285));
#2287=FACE_BOUND('',#2286,.T.);
#2288=ADVANCED_FACE('F1846',(#2287),#2276,.F.);
#2289=CARTESIAN_POINT('',(8.73926114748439,9.63718395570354,7.5));
#2290=DIRECTION('',(0.766044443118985,-0.642787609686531,0.));
#2291=DIRECTION('',(0.642787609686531,0.766044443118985,0.));
#2292=AXIS2_PLACEMENT_3D('',#2289,#2290,#2291);
#2293=PLANE('',#2292);
#2294=ORIENTED_EDGE('',*,*,#1088,.T.);
#2295=DIRECTION('',(0.,0.,-1.));
#2296=VECTOR('',#2295,1.);
#2297=CARTESIAN_POINT('',(3.59696026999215,3.50882841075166,7.5));
#2298=LINE('',#2297,#2296);
#2299=EDGE_CURVE('E530',#975,#1081,#2298,.T.);
#2300=ORIENTED_EDGE('',*,*,#2299,.F.);
#2301=ORIENTED_EDGE('',*,*,#976,.F.);
#2302=ORIENTED_EDGE('',*,*,#100,.F.);
#2303=EDGE_LOOP('',(#2294,#2300,#2301,#2302));
#2304=FACE_BOUND('',#2303,.T.);
#2305=ADVANCED_FACE('F1198',(#2304),#2293,.F.);
#2306=CARTESIAN_POINT('',(2.83091582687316,4.15161602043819,7.5));
#2307=DIRECTION('',(0.64278760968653,0.766044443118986,0.));
#2308=DIRECTION('',(-0.766044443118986,0.64278760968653,0.));
#2309=AXIS2_PLACEMENT_3D('',#2306,#2307,#2308);
#2310=PLANE('',#2309);
#2311=ORIENTED_EDGE('',*,*,#2299,.T.);
#2312=ORIENTED_EDGE('',*,*,#1082,.F.);
#2313=ORIENTED_EDGE('',*,*,#2282,.F.);
#2314=ORIENTED_EDGE('',*,*,#984,.T.);
#2315=EDGE_LOOP('',(#2311,#2312,#2313,#2314));
#2316=FACE_BOUND('',#2315,.T.);
#2317=ADVANCED_FACE('F1193',(#2316),#2310,.T.);
#2318=CARTESIAN_POINT('',(1.24025440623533,4.86947317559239,7.5));
#2319=DIRECTION('',(-0.939692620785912,0.342020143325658,0.));
#2320=DIRECTION('',(-0.342020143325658,-0.939692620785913,0.));
#2321=AXIS2_PLACEMENT_3D('',#2318,#2319,#2320);
#2322=PLANE('',#2321);
#2323=ORIENTED_EDGE('',*,*,#594,.F.);
#2324=DIRECTION('',(0.,0.,-1.));
#2325=VECTOR('',#2324,1.);
#2326=CARTESIAN_POINT('',(1.24025440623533,4.86947317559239,7.5));
#2327=LINE('',#2326,#2325);
#2328=EDGE_CURVE('E512',#587,#1050,#2327,.T.);
#2329=ORIENTED_EDGE('',*,*,#2328,.T.);
#2330=ORIENTED_EDGE('',*,*,#1051,.T.);
#2331=ORIENTED_EDGE('',*,*,#41,.F.);
#2332=EDGE_LOOP('',(#2323,#2329,#2330,#2331));
#2333=FACE_BOUND('',#2332,.T.);
#2334=ADVANCED_FACE('F1865',(#2333),#2322,.F.);
#2335=CARTESIAN_POINT('',(4.91610817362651,12.044993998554,7.5));
#2336=DIRECTION('',(0.939692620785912,-0.342020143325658,0.));
#2337=DIRECTION('',(0.342020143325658,0.939692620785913,0.));
#2338=AXIS2_PLACEMENT_3D('',#2335,#2336,#2337);
#2339=PLANE('',#2338);
#2340=ORIENTED_EDGE('',*,*,#1065,.T.);
#2341=DIRECTION('',(0.,0.,-1.));
#2342=VECTOR('',#2341,1.);
#2343=CARTESIAN_POINT('',(2.17994702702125,4.52745303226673,7.5));
#2344=LINE('',#2343,#2342);
#2345=EDGE_CURVE('E493',#579,#1058,#2344,.T.);
#2346=ORIENTED_EDGE('',*,*,#2345,.F.);
#2347=ORIENTED_EDGE('',*,*,#580,.F.);
#2348=ORIENTED_EDGE('',*,*,#73,.F.);
#2349=EDGE_LOOP('',(#2340,#2346,#2347,#2348));
#2350=FACE_BOUND('',#2349,.T.);
#2351=ADVANCED_FACE('F492',(#2350),#2339,.F.);
#2352=CARTESIAN_POINT('',(1.24025440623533,4.86947317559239,7.5));
#2353=DIRECTION('',(0.342020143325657,0.939692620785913,0.));
#2354=DIRECTION('',(-0.939692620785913,0.342020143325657,0.));
#2355=AXIS2_PLACEMENT_3D('',#2352,#2353,#2354);
#2356=PLANE('',#2355);
#2357=ORIENTED_EDGE('',*,*,#2345,.T.);
#2358=ORIENTED_EDGE('',*,*,#1059,.F.);
#2359=ORIENTED_EDGE('',*,*,#2328,.F.);
#2360=ORIENTED_EDGE('',*,*,#588,.T.);
#2361=EDGE_LOOP('',(#2357,#2358,#2359,#2360));
#2362=FACE_BOUND('',#2361,.T.);
#2363=ADVANCED_FACE('F502',(#2362),#2356,.T.);
#2364=CLOSED_SHELL('',(#60,#87,#114,#141,#168,#195,#222,#249,#276,#303,#330,#357,#384,#411,#438,
#465,#492,#545,#567,#1005,#1025,#1038,#1476,#1496,#1508,#1525,#1535,#1552,#1569,#1581,#1598,
#1615,#1627,#1644,#1661,#1673,#1690,#1707,#1719,#1736,#1753,#1765,#1782,#1799,#1811,#1828,#1845,
#1857,#1874,#1891,#1903,#1920,#1937,#1949,#1966,#1983,#1995,#2012,#2029,#2041,#2058,#2075,#2087,
#2104,#2121,#2133,#2150,#2167,#2179,#2196,#2213,#2225,#2242,#2259,#2271,#2288,#2305,#2317,#2334,
#2351,#2363));
#2365=MANIFOLD_SOLID_BREP('B2',#2364);
#2366=ADVANCED_BREP_SHAPE_REPRESENTATION('',(#18,#2365),#14);
#2367=SHAPE_DEFINITION_REPRESENTATION(#9,#2366);
ENDSEC;
END-ISO-10303-21;
